VERSION 5.7 ;
BUSBITCHARS "[]" ;
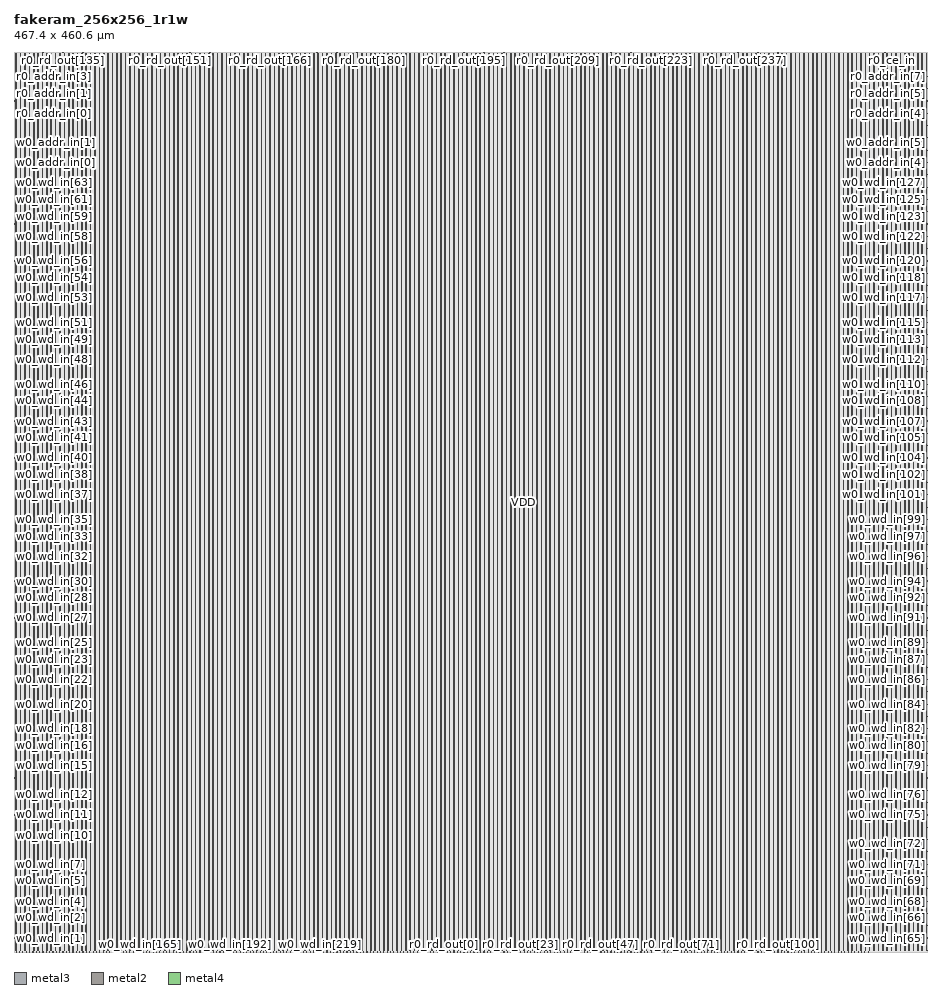
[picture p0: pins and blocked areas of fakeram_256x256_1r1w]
MACRO fakeram_256x256_1r1w
  FOREIGN fakeram_256x256_1r1w 0 0 ;
  SYMMETRY X Y R90 ;
  SIZE 467.400 BY 460.600 ;
  CLASS BLOCK ;
  PIN w0_wd_in[0]
    DIRECTION INPUT ;
    USE SIGNAL ;
    SHAPE ABUTMENT ;
    PORT
      LAYER metal3 ;
      RECT 0.000 0.805 0.210 0.875 ;
    END
  END w0_wd_in[0]
  PIN w0_wd_in[1]
    DIRECTION INPUT ;
    USE SIGNAL ;
    SHAPE ABUTMENT ;
    PORT
      LAYER metal3 ;
      RECT 0.000 7.105 0.210 7.175 ;
    END
  END w0_wd_in[1]
  PIN w0_wd_in[2]
    DIRECTION INPUT ;
    USE SIGNAL ;
    SHAPE ABUTMENT ;
    PORT
      LAYER metal3 ;
      RECT 0.000 13.405 0.210 13.475 ;
    END
  END w0_wd_in[2]
  PIN w0_wd_in[3]
    DIRECTION INPUT ;
    USE SIGNAL ;
    SHAPE ABUTMENT ;
    PORT
      LAYER metal3 ;
      RECT 0.000 19.705 0.210 19.775 ;
    END
  END w0_wd_in[3]
  PIN w0_wd_in[4]
    DIRECTION INPUT ;
    USE SIGNAL ;
    SHAPE ABUTMENT ;
    PORT
      LAYER metal3 ;
      RECT 0.000 26.005 0.210 26.075 ;
    END
  END w0_wd_in[4]
  PIN w0_wd_in[5]
    DIRECTION INPUT ;
    USE SIGNAL ;
    SHAPE ABUTMENT ;
    PORT
      LAYER metal3 ;
      RECT 0.000 32.305 0.210 32.375 ;
    END
  END w0_wd_in[5]
  PIN w0_wd_in[6]
    DIRECTION INPUT ;
    USE SIGNAL ;
    SHAPE ABUTMENT ;
    PORT
      LAYER metal3 ;
      RECT 0.000 38.605 0.210 38.675 ;
    END
  END w0_wd_in[6]
  PIN w0_wd_in[7]
    DIRECTION INPUT ;
    USE SIGNAL ;
    SHAPE ABUTMENT ;
    PORT
      LAYER metal3 ;
      RECT 0.000 44.905 0.210 44.975 ;
    END
  END w0_wd_in[7]
  PIN w0_wd_in[8]
    DIRECTION INPUT ;
    USE SIGNAL ;
    SHAPE ABUTMENT ;
    PORT
      LAYER metal3 ;
      RECT 0.000 51.205 0.210 51.275 ;
    END
  END w0_wd_in[8]
  PIN w0_wd_in[9]
    DIRECTION INPUT ;
    USE SIGNAL ;
    SHAPE ABUTMENT ;
    PORT
      LAYER metal3 ;
      RECT 0.000 57.505 0.210 57.575 ;
    END
  END w0_wd_in[9]
  PIN w0_wd_in[10]
    DIRECTION INPUT ;
    USE SIGNAL ;
    SHAPE ABUTMENT ;
    PORT
      LAYER metal3 ;
      RECT 0.000 63.805 0.210 63.875 ;
    END
  END w0_wd_in[10]
  PIN w0_wd_in[11]
    DIRECTION INPUT ;
    USE SIGNAL ;
    SHAPE ABUTMENT ;
    PORT
      LAYER metal3 ;
      RECT 0.000 70.105 0.210 70.175 ;
    END
  END w0_wd_in[11]
  PIN w0_wd_in[12]
    DIRECTION INPUT ;
    USE SIGNAL ;
    SHAPE ABUTMENT ;
    PORT
      LAYER metal3 ;
      RECT 0.000 76.405 0.210 76.475 ;
    END
  END w0_wd_in[12]
  PIN w0_wd_in[13]
    DIRECTION INPUT ;
    USE SIGNAL ;
    SHAPE ABUTMENT ;
    PORT
      LAYER metal3 ;
      RECT 0.000 82.705 0.210 82.775 ;
    END
  END w0_wd_in[13]
  PIN w0_wd_in[14]
    DIRECTION INPUT ;
    USE SIGNAL ;
    SHAPE ABUTMENT ;
    PORT
      LAYER metal3 ;
      RECT 0.000 89.005 0.210 89.075 ;
    END
  END w0_wd_in[14]
  PIN w0_wd_in[15]
    DIRECTION INPUT ;
    USE SIGNAL ;
    SHAPE ABUTMENT ;
    PORT
      LAYER metal3 ;
      RECT 0.000 95.305 0.210 95.375 ;
    END
  END w0_wd_in[15]
  PIN w0_wd_in[16]
    DIRECTION INPUT ;
    USE SIGNAL ;
    SHAPE ABUTMENT ;
    PORT
      LAYER metal3 ;
      RECT 0.000 101.605 0.210 101.675 ;
    END
  END w0_wd_in[16]
  PIN w0_wd_in[17]
    DIRECTION INPUT ;
    USE SIGNAL ;
    SHAPE ABUTMENT ;
    PORT
      LAYER metal3 ;
      RECT 0.000 107.905 0.210 107.975 ;
    END
  END w0_wd_in[17]
  PIN w0_wd_in[18]
    DIRECTION INPUT ;
    USE SIGNAL ;
    SHAPE ABUTMENT ;
    PORT
      LAYER metal3 ;
      RECT 0.000 114.205 0.210 114.275 ;
    END
  END w0_wd_in[18]
  PIN w0_wd_in[19]
    DIRECTION INPUT ;
    USE SIGNAL ;
    SHAPE ABUTMENT ;
    PORT
      LAYER metal3 ;
      RECT 0.000 120.505 0.210 120.575 ;
    END
  END w0_wd_in[19]
  PIN w0_wd_in[20]
    DIRECTION INPUT ;
    USE SIGNAL ;
    SHAPE ABUTMENT ;
    PORT
      LAYER metal3 ;
      RECT 0.000 126.805 0.210 126.875 ;
    END
  END w0_wd_in[20]
  PIN w0_wd_in[21]
    DIRECTION INPUT ;
    USE SIGNAL ;
    SHAPE ABUTMENT ;
    PORT
      LAYER metal3 ;
      RECT 0.000 133.105 0.210 133.175 ;
    END
  END w0_wd_in[21]
  PIN w0_wd_in[22]
    DIRECTION INPUT ;
    USE SIGNAL ;
    SHAPE ABUTMENT ;
    PORT
      LAYER metal3 ;
      RECT 0.000 139.405 0.210 139.475 ;
    END
  END w0_wd_in[22]
  PIN w0_wd_in[23]
    DIRECTION INPUT ;
    USE SIGNAL ;
    SHAPE ABUTMENT ;
    PORT
      LAYER metal3 ;
      RECT 0.000 145.705 0.210 145.775 ;
    END
  END w0_wd_in[23]
  PIN w0_wd_in[24]
    DIRECTION INPUT ;
    USE SIGNAL ;
    SHAPE ABUTMENT ;
    PORT
      LAYER metal3 ;
      RECT 0.000 152.005 0.210 152.075 ;
    END
  END w0_wd_in[24]
  PIN w0_wd_in[25]
    DIRECTION INPUT ;
    USE SIGNAL ;
    SHAPE ABUTMENT ;
    PORT
      LAYER metal3 ;
      RECT 0.000 158.305 0.210 158.375 ;
    END
  END w0_wd_in[25]
  PIN w0_wd_in[26]
    DIRECTION INPUT ;
    USE SIGNAL ;
    SHAPE ABUTMENT ;
    PORT
      LAYER metal3 ;
      RECT 0.000 164.605 0.210 164.675 ;
    END
  END w0_wd_in[26]
  PIN w0_wd_in[27]
    DIRECTION INPUT ;
    USE SIGNAL ;
    SHAPE ABUTMENT ;
    PORT
      LAYER metal3 ;
      RECT 0.000 170.905 0.210 170.975 ;
    END
  END w0_wd_in[27]
  PIN w0_wd_in[28]
    DIRECTION INPUT ;
    USE SIGNAL ;
    SHAPE ABUTMENT ;
    PORT
      LAYER metal3 ;
      RECT 0.000 177.205 0.210 177.275 ;
    END
  END w0_wd_in[28]
  PIN w0_wd_in[29]
    DIRECTION INPUT ;
    USE SIGNAL ;
    SHAPE ABUTMENT ;
    PORT
      LAYER metal3 ;
      RECT 0.000 183.505 0.210 183.575 ;
    END
  END w0_wd_in[29]
  PIN w0_wd_in[30]
    DIRECTION INPUT ;
    USE SIGNAL ;
    SHAPE ABUTMENT ;
    PORT
      LAYER metal3 ;
      RECT 0.000 189.805 0.210 189.875 ;
    END
  END w0_wd_in[30]
  PIN w0_wd_in[31]
    DIRECTION INPUT ;
    USE SIGNAL ;
    SHAPE ABUTMENT ;
    PORT
      LAYER metal3 ;
      RECT 0.000 196.105 0.210 196.175 ;
    END
  END w0_wd_in[31]
  PIN w0_wd_in[32]
    DIRECTION INPUT ;
    USE SIGNAL ;
    SHAPE ABUTMENT ;
    PORT
      LAYER metal3 ;
      RECT 0.000 202.405 0.210 202.475 ;
    END
  END w0_wd_in[32]
  PIN w0_wd_in[33]
    DIRECTION INPUT ;
    USE SIGNAL ;
    SHAPE ABUTMENT ;
    PORT
      LAYER metal3 ;
      RECT 0.000 208.705 0.210 208.775 ;
    END
  END w0_wd_in[33]
  PIN w0_wd_in[34]
    DIRECTION INPUT ;
    USE SIGNAL ;
    SHAPE ABUTMENT ;
    PORT
      LAYER metal3 ;
      RECT 0.000 215.005 0.210 215.075 ;
    END
  END w0_wd_in[34]
  PIN w0_wd_in[35]
    DIRECTION INPUT ;
    USE SIGNAL ;
    SHAPE ABUTMENT ;
    PORT
      LAYER metal3 ;
      RECT 0.000 221.305 0.210 221.375 ;
    END
  END w0_wd_in[35]
  PIN w0_wd_in[36]
    DIRECTION INPUT ;
    USE SIGNAL ;
    SHAPE ABUTMENT ;
    PORT
      LAYER metal3 ;
      RECT 0.000 227.605 0.210 227.675 ;
    END
  END w0_wd_in[36]
  PIN w0_wd_in[37]
    DIRECTION INPUT ;
    USE SIGNAL ;
    SHAPE ABUTMENT ;
    PORT
      LAYER metal3 ;
      RECT 0.000 233.905 0.210 233.975 ;
    END
  END w0_wd_in[37]
  PIN w0_wd_in[38]
    DIRECTION INPUT ;
    USE SIGNAL ;
    SHAPE ABUTMENT ;
    PORT
      LAYER metal3 ;
      RECT 0.000 240.205 0.210 240.275 ;
    END
  END w0_wd_in[38]
  PIN w0_wd_in[39]
    DIRECTION INPUT ;
    USE SIGNAL ;
    SHAPE ABUTMENT ;
    PORT
      LAYER metal3 ;
      RECT 0.000 246.505 0.210 246.575 ;
    END
  END w0_wd_in[39]
  PIN w0_wd_in[40]
    DIRECTION INPUT ;
    USE SIGNAL ;
    SHAPE ABUTMENT ;
    PORT
      LAYER metal3 ;
      RECT 0.000 252.805 0.210 252.875 ;
    END
  END w0_wd_in[40]
  PIN w0_wd_in[41]
    DIRECTION INPUT ;
    USE SIGNAL ;
    SHAPE ABUTMENT ;
    PORT
      LAYER metal3 ;
      RECT 0.000 259.105 0.210 259.175 ;
    END
  END w0_wd_in[41]
  PIN w0_wd_in[42]
    DIRECTION INPUT ;
    USE SIGNAL ;
    SHAPE ABUTMENT ;
    PORT
      LAYER metal3 ;
      RECT 0.000 265.405 0.210 265.475 ;
    END
  END w0_wd_in[42]
  PIN w0_wd_in[43]
    DIRECTION INPUT ;
    USE SIGNAL ;
    SHAPE ABUTMENT ;
    PORT
      LAYER metal3 ;
      RECT 0.000 271.705 0.210 271.775 ;
    END
  END w0_wd_in[43]
  PIN w0_wd_in[44]
    DIRECTION INPUT ;
    USE SIGNAL ;
    SHAPE ABUTMENT ;
    PORT
      LAYER metal3 ;
      RECT 0.000 278.005 0.210 278.075 ;
    END
  END w0_wd_in[44]
  PIN w0_wd_in[45]
    DIRECTION INPUT ;
    USE SIGNAL ;
    SHAPE ABUTMENT ;
    PORT
      LAYER metal3 ;
      RECT 0.000 284.305 0.210 284.375 ;
    END
  END w0_wd_in[45]
  PIN w0_wd_in[46]
    DIRECTION INPUT ;
    USE SIGNAL ;
    SHAPE ABUTMENT ;
    PORT
      LAYER metal3 ;
      RECT 0.000 290.605 0.210 290.675 ;
    END
  END w0_wd_in[46]
  PIN w0_wd_in[47]
    DIRECTION INPUT ;
    USE SIGNAL ;
    SHAPE ABUTMENT ;
    PORT
      LAYER metal3 ;
      RECT 0.000 296.905 0.210 296.975 ;
    END
  END w0_wd_in[47]
  PIN w0_wd_in[48]
    DIRECTION INPUT ;
    USE SIGNAL ;
    SHAPE ABUTMENT ;
    PORT
      LAYER metal3 ;
      RECT 0.000 303.205 0.210 303.275 ;
    END
  END w0_wd_in[48]
  PIN w0_wd_in[49]
    DIRECTION INPUT ;
    USE SIGNAL ;
    SHAPE ABUTMENT ;
    PORT
      LAYER metal3 ;
      RECT 0.000 309.505 0.210 309.575 ;
    END
  END w0_wd_in[49]
  PIN w0_wd_in[50]
    DIRECTION INPUT ;
    USE SIGNAL ;
    SHAPE ABUTMENT ;
    PORT
      LAYER metal3 ;
      RECT 0.000 315.805 0.210 315.875 ;
    END
  END w0_wd_in[50]
  PIN w0_wd_in[51]
    DIRECTION INPUT ;
    USE SIGNAL ;
    SHAPE ABUTMENT ;
    PORT
      LAYER metal3 ;
      RECT 0.000 322.105 0.210 322.175 ;
    END
  END w0_wd_in[51]
  PIN w0_wd_in[52]
    DIRECTION INPUT ;
    USE SIGNAL ;
    SHAPE ABUTMENT ;
    PORT
      LAYER metal3 ;
      RECT 0.000 328.405 0.210 328.475 ;
    END
  END w0_wd_in[52]
  PIN w0_wd_in[53]
    DIRECTION INPUT ;
    USE SIGNAL ;
    SHAPE ABUTMENT ;
    PORT
      LAYER metal3 ;
      RECT 0.000 334.705 0.210 334.775 ;
    END
  END w0_wd_in[53]
  PIN w0_wd_in[54]
    DIRECTION INPUT ;
    USE SIGNAL ;
    SHAPE ABUTMENT ;
    PORT
      LAYER metal3 ;
      RECT 0.000 341.005 0.210 341.075 ;
    END
  END w0_wd_in[54]
  PIN w0_wd_in[55]
    DIRECTION INPUT ;
    USE SIGNAL ;
    SHAPE ABUTMENT ;
    PORT
      LAYER metal3 ;
      RECT 0.000 347.305 0.210 347.375 ;
    END
  END w0_wd_in[55]
  PIN w0_wd_in[56]
    DIRECTION INPUT ;
    USE SIGNAL ;
    SHAPE ABUTMENT ;
    PORT
      LAYER metal3 ;
      RECT 0.000 353.605 0.210 353.675 ;
    END
  END w0_wd_in[56]
  PIN w0_wd_in[57]
    DIRECTION INPUT ;
    USE SIGNAL ;
    SHAPE ABUTMENT ;
    PORT
      LAYER metal3 ;
      RECT 0.000 359.905 0.210 359.975 ;
    END
  END w0_wd_in[57]
  PIN w0_wd_in[58]
    DIRECTION INPUT ;
    USE SIGNAL ;
    SHAPE ABUTMENT ;
    PORT
      LAYER metal3 ;
      RECT 0.000 366.205 0.210 366.275 ;
    END
  END w0_wd_in[58]
  PIN w0_wd_in[59]
    DIRECTION INPUT ;
    USE SIGNAL ;
    SHAPE ABUTMENT ;
    PORT
      LAYER metal3 ;
      RECT 0.000 372.505 0.210 372.575 ;
    END
  END w0_wd_in[59]
  PIN w0_wd_in[60]
    DIRECTION INPUT ;
    USE SIGNAL ;
    SHAPE ABUTMENT ;
    PORT
      LAYER metal3 ;
      RECT 0.000 378.805 0.210 378.875 ;
    END
  END w0_wd_in[60]
  PIN w0_wd_in[61]
    DIRECTION INPUT ;
    USE SIGNAL ;
    SHAPE ABUTMENT ;
    PORT
      LAYER metal3 ;
      RECT 0.000 385.105 0.210 385.175 ;
    END
  END w0_wd_in[61]
  PIN w0_wd_in[62]
    DIRECTION INPUT ;
    USE SIGNAL ;
    SHAPE ABUTMENT ;
    PORT
      LAYER metal3 ;
      RECT 0.000 391.405 0.210 391.475 ;
    END
  END w0_wd_in[62]
  PIN w0_wd_in[63]
    DIRECTION INPUT ;
    USE SIGNAL ;
    SHAPE ABUTMENT ;
    PORT
      LAYER metal3 ;
      RECT 0.000 397.705 0.210 397.775 ;
    END
  END w0_wd_in[63]
  PIN w0_wd_in[64]
    DIRECTION INPUT ;
    USE SIGNAL ;
    SHAPE ABUTMENT ;
    PORT
      LAYER metal3 ;
      RECT 467.190 0.805 467.400 0.875 ;
    END
  END w0_wd_in[64]
  PIN w0_wd_in[65]
    DIRECTION INPUT ;
    USE SIGNAL ;
    SHAPE ABUTMENT ;
    PORT
      LAYER metal3 ;
      RECT 467.190 7.105 467.400 7.175 ;
    END
  END w0_wd_in[65]
  PIN w0_wd_in[66]
    DIRECTION INPUT ;
    USE SIGNAL ;
    SHAPE ABUTMENT ;
    PORT
      LAYER metal3 ;
      RECT 467.190 13.405 467.400 13.475 ;
    END
  END w0_wd_in[66]
  PIN w0_wd_in[67]
    DIRECTION INPUT ;
    USE SIGNAL ;
    SHAPE ABUTMENT ;
    PORT
      LAYER metal3 ;
      RECT 467.190 19.705 467.400 19.775 ;
    END
  END w0_wd_in[67]
  PIN w0_wd_in[68]
    DIRECTION INPUT ;
    USE SIGNAL ;
    SHAPE ABUTMENT ;
    PORT
      LAYER metal3 ;
      RECT 467.190 26.005 467.400 26.075 ;
    END
  END w0_wd_in[68]
  PIN w0_wd_in[69]
    DIRECTION INPUT ;
    USE SIGNAL ;
    SHAPE ABUTMENT ;
    PORT
      LAYER metal3 ;
      RECT 467.190 32.305 467.400 32.375 ;
    END
  END w0_wd_in[69]
  PIN w0_wd_in[70]
    DIRECTION INPUT ;
    USE SIGNAL ;
    SHAPE ABUTMENT ;
    PORT
      LAYER metal3 ;
      RECT 467.190 38.605 467.400 38.675 ;
    END
  END w0_wd_in[70]
  PIN w0_wd_in[71]
    DIRECTION INPUT ;
    USE SIGNAL ;
    SHAPE ABUTMENT ;
    PORT
      LAYER metal3 ;
      RECT 467.190 44.905 467.400 44.975 ;
    END
  END w0_wd_in[71]
  PIN w0_wd_in[72]
    DIRECTION INPUT ;
    USE SIGNAL ;
    SHAPE ABUTMENT ;
    PORT
      LAYER metal3 ;
      RECT 467.190 51.205 467.400 51.275 ;
    END
  END w0_wd_in[72]
  PIN w0_wd_in[73]
    DIRECTION INPUT ;
    USE SIGNAL ;
    SHAPE ABUTMENT ;
    PORT
      LAYER metal3 ;
      RECT 467.190 57.505 467.400 57.575 ;
    END
  END w0_wd_in[73]
  PIN w0_wd_in[74]
    DIRECTION INPUT ;
    USE SIGNAL ;
    SHAPE ABUTMENT ;
    PORT
      LAYER metal3 ;
      RECT 467.190 63.805 467.400 63.875 ;
    END
  END w0_wd_in[74]
  PIN w0_wd_in[75]
    DIRECTION INPUT ;
    USE SIGNAL ;
    SHAPE ABUTMENT ;
    PORT
      LAYER metal3 ;
      RECT 467.190 70.105 467.400 70.175 ;
    END
  END w0_wd_in[75]
  PIN w0_wd_in[76]
    DIRECTION INPUT ;
    USE SIGNAL ;
    SHAPE ABUTMENT ;
    PORT
      LAYER metal3 ;
      RECT 467.190 76.405 467.400 76.475 ;
    END
  END w0_wd_in[76]
  PIN w0_wd_in[77]
    DIRECTION INPUT ;
    USE SIGNAL ;
    SHAPE ABUTMENT ;
    PORT
      LAYER metal3 ;
      RECT 467.190 82.705 467.400 82.775 ;
    END
  END w0_wd_in[77]
  PIN w0_wd_in[78]
    DIRECTION INPUT ;
    USE SIGNAL ;
    SHAPE ABUTMENT ;
    PORT
      LAYER metal3 ;
      RECT 467.190 89.005 467.400 89.075 ;
    END
  END w0_wd_in[78]
  PIN w0_wd_in[79]
    DIRECTION INPUT ;
    USE SIGNAL ;
    SHAPE ABUTMENT ;
    PORT
      LAYER metal3 ;
      RECT 467.190 95.305 467.400 95.375 ;
    END
  END w0_wd_in[79]
  PIN w0_wd_in[80]
    DIRECTION INPUT ;
    USE SIGNAL ;
    SHAPE ABUTMENT ;
    PORT
      LAYER metal3 ;
      RECT 467.190 101.605 467.400 101.675 ;
    END
  END w0_wd_in[80]
  PIN w0_wd_in[81]
    DIRECTION INPUT ;
    USE SIGNAL ;
    SHAPE ABUTMENT ;
    PORT
      LAYER metal3 ;
      RECT 467.190 107.905 467.400 107.975 ;
    END
  END w0_wd_in[81]
  PIN w0_wd_in[82]
    DIRECTION INPUT ;
    USE SIGNAL ;
    SHAPE ABUTMENT ;
    PORT
      LAYER metal3 ;
      RECT 467.190 114.205 467.400 114.275 ;
    END
  END w0_wd_in[82]
  PIN w0_wd_in[83]
    DIRECTION INPUT ;
    USE SIGNAL ;
    SHAPE ABUTMENT ;
    PORT
      LAYER metal3 ;
      RECT 467.190 120.505 467.400 120.575 ;
    END
  END w0_wd_in[83]
  PIN w0_wd_in[84]
    DIRECTION INPUT ;
    USE SIGNAL ;
    SHAPE ABUTMENT ;
    PORT
      LAYER metal3 ;
      RECT 467.190 126.805 467.400 126.875 ;
    END
  END w0_wd_in[84]
  PIN w0_wd_in[85]
    DIRECTION INPUT ;
    USE SIGNAL ;
    SHAPE ABUTMENT ;
    PORT
      LAYER metal3 ;
      RECT 467.190 133.105 467.400 133.175 ;
    END
  END w0_wd_in[85]
  PIN w0_wd_in[86]
    DIRECTION INPUT ;
    USE SIGNAL ;
    SHAPE ABUTMENT ;
    PORT
      LAYER metal3 ;
      RECT 467.190 139.405 467.400 139.475 ;
    END
  END w0_wd_in[86]
  PIN w0_wd_in[87]
    DIRECTION INPUT ;
    USE SIGNAL ;
    SHAPE ABUTMENT ;
    PORT
      LAYER metal3 ;
      RECT 467.190 145.705 467.400 145.775 ;
    END
  END w0_wd_in[87]
  PIN w0_wd_in[88]
    DIRECTION INPUT ;
    USE SIGNAL ;
    SHAPE ABUTMENT ;
    PORT
      LAYER metal3 ;
      RECT 467.190 152.005 467.400 152.075 ;
    END
  END w0_wd_in[88]
  PIN w0_wd_in[89]
    DIRECTION INPUT ;
    USE SIGNAL ;
    SHAPE ABUTMENT ;
    PORT
      LAYER metal3 ;
      RECT 467.190 158.305 467.400 158.375 ;
    END
  END w0_wd_in[89]
  PIN w0_wd_in[90]
    DIRECTION INPUT ;
    USE SIGNAL ;
    SHAPE ABUTMENT ;
    PORT
      LAYER metal3 ;
      RECT 467.190 164.605 467.400 164.675 ;
    END
  END w0_wd_in[90]
  PIN w0_wd_in[91]
    DIRECTION INPUT ;
    USE SIGNAL ;
    SHAPE ABUTMENT ;
    PORT
      LAYER metal3 ;
      RECT 467.190 170.905 467.400 170.975 ;
    END
  END w0_wd_in[91]
  PIN w0_wd_in[92]
    DIRECTION INPUT ;
    USE SIGNAL ;
    SHAPE ABUTMENT ;
    PORT
      LAYER metal3 ;
      RECT 467.190 177.205 467.400 177.275 ;
    END
  END w0_wd_in[92]
  PIN w0_wd_in[93]
    DIRECTION INPUT ;
    USE SIGNAL ;
    SHAPE ABUTMENT ;
    PORT
      LAYER metal3 ;
      RECT 467.190 183.505 467.400 183.575 ;
    END
  END w0_wd_in[93]
  PIN w0_wd_in[94]
    DIRECTION INPUT ;
    USE SIGNAL ;
    SHAPE ABUTMENT ;
    PORT
      LAYER metal3 ;
      RECT 467.190 189.805 467.400 189.875 ;
    END
  END w0_wd_in[94]
  PIN w0_wd_in[95]
    DIRECTION INPUT ;
    USE SIGNAL ;
    SHAPE ABUTMENT ;
    PORT
      LAYER metal3 ;
      RECT 467.190 196.105 467.400 196.175 ;
    END
  END w0_wd_in[95]
  PIN w0_wd_in[96]
    DIRECTION INPUT ;
    USE SIGNAL ;
    SHAPE ABUTMENT ;
    PORT
      LAYER metal3 ;
      RECT 467.190 202.405 467.400 202.475 ;
    END
  END w0_wd_in[96]
  PIN w0_wd_in[97]
    DIRECTION INPUT ;
    USE SIGNAL ;
    SHAPE ABUTMENT ;
    PORT
      LAYER metal3 ;
      RECT 467.190 208.705 467.400 208.775 ;
    END
  END w0_wd_in[97]
  PIN w0_wd_in[98]
    DIRECTION INPUT ;
    USE SIGNAL ;
    SHAPE ABUTMENT ;
    PORT
      LAYER metal3 ;
      RECT 467.190 215.005 467.400 215.075 ;
    END
  END w0_wd_in[98]
  PIN w0_wd_in[99]
    DIRECTION INPUT ;
    USE SIGNAL ;
    SHAPE ABUTMENT ;
    PORT
      LAYER metal3 ;
      RECT 467.190 221.305 467.400 221.375 ;
    END
  END w0_wd_in[99]
  PIN w0_wd_in[100]
    DIRECTION INPUT ;
    USE SIGNAL ;
    SHAPE ABUTMENT ;
    PORT
      LAYER metal3 ;
      RECT 467.190 227.605 467.400 227.675 ;
    END
  END w0_wd_in[100]
  PIN w0_wd_in[101]
    DIRECTION INPUT ;
    USE SIGNAL ;
    SHAPE ABUTMENT ;
    PORT
      LAYER metal3 ;
      RECT 467.190 233.905 467.400 233.975 ;
    END
  END w0_wd_in[101]
  PIN w0_wd_in[102]
    DIRECTION INPUT ;
    USE SIGNAL ;
    SHAPE ABUTMENT ;
    PORT
      LAYER metal3 ;
      RECT 467.190 240.205 467.400 240.275 ;
    END
  END w0_wd_in[102]
  PIN w0_wd_in[103]
    DIRECTION INPUT ;
    USE SIGNAL ;
    SHAPE ABUTMENT ;
    PORT
      LAYER metal3 ;
      RECT 467.190 246.505 467.400 246.575 ;
    END
  END w0_wd_in[103]
  PIN w0_wd_in[104]
    DIRECTION INPUT ;
    USE SIGNAL ;
    SHAPE ABUTMENT ;
    PORT
      LAYER metal3 ;
      RECT 467.190 252.805 467.400 252.875 ;
    END
  END w0_wd_in[104]
  PIN w0_wd_in[105]
    DIRECTION INPUT ;
    USE SIGNAL ;
    SHAPE ABUTMENT ;
    PORT
      LAYER metal3 ;
      RECT 467.190 259.105 467.400 259.175 ;
    END
  END w0_wd_in[105]
  PIN w0_wd_in[106]
    DIRECTION INPUT ;
    USE SIGNAL ;
    SHAPE ABUTMENT ;
    PORT
      LAYER metal3 ;
      RECT 467.190 265.405 467.400 265.475 ;
    END
  END w0_wd_in[106]
  PIN w0_wd_in[107]
    DIRECTION INPUT ;
    USE SIGNAL ;
    SHAPE ABUTMENT ;
    PORT
      LAYER metal3 ;
      RECT 467.190 271.705 467.400 271.775 ;
    END
  END w0_wd_in[107]
  PIN w0_wd_in[108]
    DIRECTION INPUT ;
    USE SIGNAL ;
    SHAPE ABUTMENT ;
    PORT
      LAYER metal3 ;
      RECT 467.190 278.005 467.400 278.075 ;
    END
  END w0_wd_in[108]
  PIN w0_wd_in[109]
    DIRECTION INPUT ;
    USE SIGNAL ;
    SHAPE ABUTMENT ;
    PORT
      LAYER metal3 ;
      RECT 467.190 284.305 467.400 284.375 ;
    END
  END w0_wd_in[109]
  PIN w0_wd_in[110]
    DIRECTION INPUT ;
    USE SIGNAL ;
    SHAPE ABUTMENT ;
    PORT
      LAYER metal3 ;
      RECT 467.190 290.605 467.400 290.675 ;
    END
  END w0_wd_in[110]
  PIN w0_wd_in[111]
    DIRECTION INPUT ;
    USE SIGNAL ;
    SHAPE ABUTMENT ;
    PORT
      LAYER metal3 ;
      RECT 467.190 296.905 467.400 296.975 ;
    END
  END w0_wd_in[111]
  PIN w0_wd_in[112]
    DIRECTION INPUT ;
    USE SIGNAL ;
    SHAPE ABUTMENT ;
    PORT
      LAYER metal3 ;
      RECT 467.190 303.205 467.400 303.275 ;
    END
  END w0_wd_in[112]
  PIN w0_wd_in[113]
    DIRECTION INPUT ;
    USE SIGNAL ;
    SHAPE ABUTMENT ;
    PORT
      LAYER metal3 ;
      RECT 467.190 309.505 467.400 309.575 ;
    END
  END w0_wd_in[113]
  PIN w0_wd_in[114]
    DIRECTION INPUT ;
    USE SIGNAL ;
    SHAPE ABUTMENT ;
    PORT
      LAYER metal3 ;
      RECT 467.190 315.805 467.400 315.875 ;
    END
  END w0_wd_in[114]
  PIN w0_wd_in[115]
    DIRECTION INPUT ;
    USE SIGNAL ;
    SHAPE ABUTMENT ;
    PORT
      LAYER metal3 ;
      RECT 467.190 322.105 467.400 322.175 ;
    END
  END w0_wd_in[115]
  PIN w0_wd_in[116]
    DIRECTION INPUT ;
    USE SIGNAL ;
    SHAPE ABUTMENT ;
    PORT
      LAYER metal3 ;
      RECT 467.190 328.405 467.400 328.475 ;
    END
  END w0_wd_in[116]
  PIN w0_wd_in[117]
    DIRECTION INPUT ;
    USE SIGNAL ;
    SHAPE ABUTMENT ;
    PORT
      LAYER metal3 ;
      RECT 467.190 334.705 467.400 334.775 ;
    END
  END w0_wd_in[117]
  PIN w0_wd_in[118]
    DIRECTION INPUT ;
    USE SIGNAL ;
    SHAPE ABUTMENT ;
    PORT
      LAYER metal3 ;
      RECT 467.190 341.005 467.400 341.075 ;
    END
  END w0_wd_in[118]
  PIN w0_wd_in[119]
    DIRECTION INPUT ;
    USE SIGNAL ;
    SHAPE ABUTMENT ;
    PORT
      LAYER metal3 ;
      RECT 467.190 347.305 467.400 347.375 ;
    END
  END w0_wd_in[119]
  PIN w0_wd_in[120]
    DIRECTION INPUT ;
    USE SIGNAL ;
    SHAPE ABUTMENT ;
    PORT
      LAYER metal3 ;
      RECT 467.190 353.605 467.400 353.675 ;
    END
  END w0_wd_in[120]
  PIN w0_wd_in[121]
    DIRECTION INPUT ;
    USE SIGNAL ;
    SHAPE ABUTMENT ;
    PORT
      LAYER metal3 ;
      RECT 467.190 359.905 467.400 359.975 ;
    END
  END w0_wd_in[121]
  PIN w0_wd_in[122]
    DIRECTION INPUT ;
    USE SIGNAL ;
    SHAPE ABUTMENT ;
    PORT
      LAYER metal3 ;
      RECT 467.190 366.205 467.400 366.275 ;
    END
  END w0_wd_in[122]
  PIN w0_wd_in[123]
    DIRECTION INPUT ;
    USE SIGNAL ;
    SHAPE ABUTMENT ;
    PORT
      LAYER metal3 ;
      RECT 467.190 372.505 467.400 372.575 ;
    END
  END w0_wd_in[123]
  PIN w0_wd_in[124]
    DIRECTION INPUT ;
    USE SIGNAL ;
    SHAPE ABUTMENT ;
    PORT
      LAYER metal3 ;
      RECT 467.190 378.805 467.400 378.875 ;
    END
  END w0_wd_in[124]
  PIN w0_wd_in[125]
    DIRECTION INPUT ;
    USE SIGNAL ;
    SHAPE ABUTMENT ;
    PORT
      LAYER metal3 ;
      RECT 467.190 385.105 467.400 385.175 ;
    END
  END w0_wd_in[125]
  PIN w0_wd_in[126]
    DIRECTION INPUT ;
    USE SIGNAL ;
    SHAPE ABUTMENT ;
    PORT
      LAYER metal3 ;
      RECT 467.190 391.405 467.400 391.475 ;
    END
  END w0_wd_in[126]
  PIN w0_wd_in[127]
    DIRECTION INPUT ;
    USE SIGNAL ;
    SHAPE ABUTMENT ;
    PORT
      LAYER metal3 ;
      RECT 467.190 397.705 467.400 397.775 ;
    END
  END w0_wd_in[127]
  PIN w0_wd_in[128]
    DIRECTION OUTPUT ;
    USE SIGNAL ;
    SHAPE ABUTMENT ;
    PORT
      LAYER metal2 ;
      RECT 1.105 0.000 1.175 0.210 ;
    END
  END w0_wd_in[128]
  PIN w0_wd_in[129]
    DIRECTION OUTPUT ;
    USE SIGNAL ;
    SHAPE ABUTMENT ;
    PORT
      LAYER metal2 ;
      RECT 2.815 0.000 2.885 0.210 ;
    END
  END w0_wd_in[129]
  PIN w0_wd_in[130]
    DIRECTION OUTPUT ;
    USE SIGNAL ;
    SHAPE ABUTMENT ;
    PORT
      LAYER metal2 ;
      RECT 4.525 0.000 4.595 0.210 ;
    END
  END w0_wd_in[130]
  PIN w0_wd_in[131]
    DIRECTION OUTPUT ;
    USE SIGNAL ;
    SHAPE ABUTMENT ;
    PORT
      LAYER metal2 ;
      RECT 6.235 0.000 6.305 0.210 ;
    END
  END w0_wd_in[131]
  PIN w0_wd_in[132]
    DIRECTION OUTPUT ;
    USE SIGNAL ;
    SHAPE ABUTMENT ;
    PORT
      LAYER metal2 ;
      RECT 7.945 0.000 8.015 0.210 ;
    END
  END w0_wd_in[132]
  PIN w0_wd_in[133]
    DIRECTION OUTPUT ;
    USE SIGNAL ;
    SHAPE ABUTMENT ;
    PORT
      LAYER metal2 ;
      RECT 9.655 0.000 9.725 0.210 ;
    END
  END w0_wd_in[133]
  PIN w0_wd_in[134]
    DIRECTION OUTPUT ;
    USE SIGNAL ;
    SHAPE ABUTMENT ;
    PORT
      LAYER metal2 ;
      RECT 11.365 0.000 11.435 0.210 ;
    END
  END w0_wd_in[134]
  PIN w0_wd_in[135]
    DIRECTION OUTPUT ;
    USE SIGNAL ;
    SHAPE ABUTMENT ;
    PORT
      LAYER metal2 ;
      RECT 13.075 0.000 13.145 0.210 ;
    END
  END w0_wd_in[135]
  PIN w0_wd_in[136]
    DIRECTION OUTPUT ;
    USE SIGNAL ;
    SHAPE ABUTMENT ;
    PORT
      LAYER metal2 ;
      RECT 14.785 0.000 14.855 0.210 ;
    END
  END w0_wd_in[136]
  PIN w0_wd_in[137]
    DIRECTION OUTPUT ;
    USE SIGNAL ;
    SHAPE ABUTMENT ;
    PORT
      LAYER metal2 ;
      RECT 16.495 0.000 16.565 0.210 ;
    END
  END w0_wd_in[137]
  PIN w0_wd_in[138]
    DIRECTION OUTPUT ;
    USE SIGNAL ;
    SHAPE ABUTMENT ;
    PORT
      LAYER metal2 ;
      RECT 18.205 0.000 18.275 0.210 ;
    END
  END w0_wd_in[138]
  PIN w0_wd_in[139]
    DIRECTION OUTPUT ;
    USE SIGNAL ;
    SHAPE ABUTMENT ;
    PORT
      LAYER metal2 ;
      RECT 19.915 0.000 19.985 0.210 ;
    END
  END w0_wd_in[139]
  PIN w0_wd_in[140]
    DIRECTION OUTPUT ;
    USE SIGNAL ;
    SHAPE ABUTMENT ;
    PORT
      LAYER metal2 ;
      RECT 21.625 0.000 21.695 0.210 ;
    END
  END w0_wd_in[140]
  PIN w0_wd_in[141]
    DIRECTION OUTPUT ;
    USE SIGNAL ;
    SHAPE ABUTMENT ;
    PORT
      LAYER metal2 ;
      RECT 23.335 0.000 23.405 0.210 ;
    END
  END w0_wd_in[141]
  PIN w0_wd_in[142]
    DIRECTION OUTPUT ;
    USE SIGNAL ;
    SHAPE ABUTMENT ;
    PORT
      LAYER metal2 ;
      RECT 25.045 0.000 25.115 0.210 ;
    END
  END w0_wd_in[142]
  PIN w0_wd_in[143]
    DIRECTION OUTPUT ;
    USE SIGNAL ;
    SHAPE ABUTMENT ;
    PORT
      LAYER metal2 ;
      RECT 26.755 0.000 26.825 0.210 ;
    END
  END w0_wd_in[143]
  PIN w0_wd_in[144]
    DIRECTION OUTPUT ;
    USE SIGNAL ;
    SHAPE ABUTMENT ;
    PORT
      LAYER metal2 ;
      RECT 28.465 0.000 28.535 0.210 ;
    END
  END w0_wd_in[144]
  PIN w0_wd_in[145]
    DIRECTION OUTPUT ;
    USE SIGNAL ;
    SHAPE ABUTMENT ;
    PORT
      LAYER metal2 ;
      RECT 30.175 0.000 30.245 0.210 ;
    END
  END w0_wd_in[145]
  PIN w0_wd_in[146]
    DIRECTION OUTPUT ;
    USE SIGNAL ;
    SHAPE ABUTMENT ;
    PORT
      LAYER metal2 ;
      RECT 31.885 0.000 31.955 0.210 ;
    END
  END w0_wd_in[146]
  PIN w0_wd_in[147]
    DIRECTION OUTPUT ;
    USE SIGNAL ;
    SHAPE ABUTMENT ;
    PORT
      LAYER metal2 ;
      RECT 33.595 0.000 33.665 0.210 ;
    END
  END w0_wd_in[147]
  PIN w0_wd_in[148]
    DIRECTION OUTPUT ;
    USE SIGNAL ;
    SHAPE ABUTMENT ;
    PORT
      LAYER metal2 ;
      RECT 35.305 0.000 35.375 0.210 ;
    END
  END w0_wd_in[148]
  PIN w0_wd_in[149]
    DIRECTION OUTPUT ;
    USE SIGNAL ;
    SHAPE ABUTMENT ;
    PORT
      LAYER metal2 ;
      RECT 37.015 0.000 37.085 0.210 ;
    END
  END w0_wd_in[149]
  PIN w0_wd_in[150]
    DIRECTION OUTPUT ;
    USE SIGNAL ;
    SHAPE ABUTMENT ;
    PORT
      LAYER metal2 ;
      RECT 38.725 0.000 38.795 0.210 ;
    END
  END w0_wd_in[150]
  PIN w0_wd_in[151]
    DIRECTION OUTPUT ;
    USE SIGNAL ;
    SHAPE ABUTMENT ;
    PORT
      LAYER metal2 ;
      RECT 40.435 0.000 40.505 0.210 ;
    END
  END w0_wd_in[151]
  PIN w0_wd_in[152]
    DIRECTION OUTPUT ;
    USE SIGNAL ;
    SHAPE ABUTMENT ;
    PORT
      LAYER metal2 ;
      RECT 42.145 0.000 42.215 0.210 ;
    END
  END w0_wd_in[152]
  PIN w0_wd_in[153]
    DIRECTION OUTPUT ;
    USE SIGNAL ;
    SHAPE ABUTMENT ;
    PORT
      LAYER metal2 ;
      RECT 43.855 0.000 43.925 0.210 ;
    END
  END w0_wd_in[153]
  PIN w0_wd_in[154]
    DIRECTION OUTPUT ;
    USE SIGNAL ;
    SHAPE ABUTMENT ;
    PORT
      LAYER metal2 ;
      RECT 45.565 0.000 45.635 0.210 ;
    END
  END w0_wd_in[154]
  PIN w0_wd_in[155]
    DIRECTION OUTPUT ;
    USE SIGNAL ;
    SHAPE ABUTMENT ;
    PORT
      LAYER metal2 ;
      RECT 47.275 0.000 47.345 0.210 ;
    END
  END w0_wd_in[155]
  PIN w0_wd_in[156]
    DIRECTION OUTPUT ;
    USE SIGNAL ;
    SHAPE ABUTMENT ;
    PORT
      LAYER metal2 ;
      RECT 48.985 0.000 49.055 0.210 ;
    END
  END w0_wd_in[156]
  PIN w0_wd_in[157]
    DIRECTION OUTPUT ;
    USE SIGNAL ;
    SHAPE ABUTMENT ;
    PORT
      LAYER metal2 ;
      RECT 50.695 0.000 50.765 0.210 ;
    END
  END w0_wd_in[157]
  PIN w0_wd_in[158]
    DIRECTION OUTPUT ;
    USE SIGNAL ;
    SHAPE ABUTMENT ;
    PORT
      LAYER metal2 ;
      RECT 52.405 0.000 52.475 0.210 ;
    END
  END w0_wd_in[158]
  PIN w0_wd_in[159]
    DIRECTION OUTPUT ;
    USE SIGNAL ;
    SHAPE ABUTMENT ;
    PORT
      LAYER metal2 ;
      RECT 54.115 0.000 54.185 0.210 ;
    END
  END w0_wd_in[159]
  PIN w0_wd_in[160]
    DIRECTION OUTPUT ;
    USE SIGNAL ;
    SHAPE ABUTMENT ;
    PORT
      LAYER metal2 ;
      RECT 55.825 0.000 55.895 0.210 ;
    END
  END w0_wd_in[160]
  PIN w0_wd_in[161]
    DIRECTION OUTPUT ;
    USE SIGNAL ;
    SHAPE ABUTMENT ;
    PORT
      LAYER metal2 ;
      RECT 57.535 0.000 57.605 0.210 ;
    END
  END w0_wd_in[161]
  PIN w0_wd_in[162]
    DIRECTION OUTPUT ;
    USE SIGNAL ;
    SHAPE ABUTMENT ;
    PORT
      LAYER metal2 ;
      RECT 59.245 0.000 59.315 0.210 ;
    END
  END w0_wd_in[162]
  PIN w0_wd_in[163]
    DIRECTION OUTPUT ;
    USE SIGNAL ;
    SHAPE ABUTMENT ;
    PORT
      LAYER metal2 ;
      RECT 60.955 0.000 61.025 0.210 ;
    END
  END w0_wd_in[163]
  PIN w0_wd_in[164]
    DIRECTION OUTPUT ;
    USE SIGNAL ;
    SHAPE ABUTMENT ;
    PORT
      LAYER metal2 ;
      RECT 62.665 0.000 62.735 0.210 ;
    END
  END w0_wd_in[164]
  PIN w0_wd_in[165]
    DIRECTION OUTPUT ;
    USE SIGNAL ;
    SHAPE ABUTMENT ;
    PORT
      LAYER metal2 ;
      RECT 64.375 0.000 64.445 0.210 ;
    END
  END w0_wd_in[165]
  PIN w0_wd_in[166]
    DIRECTION OUTPUT ;
    USE SIGNAL ;
    SHAPE ABUTMENT ;
    PORT
      LAYER metal2 ;
      RECT 66.085 0.000 66.155 0.210 ;
    END
  END w0_wd_in[166]
  PIN w0_wd_in[167]
    DIRECTION OUTPUT ;
    USE SIGNAL ;
    SHAPE ABUTMENT ;
    PORT
      LAYER metal2 ;
      RECT 67.795 0.000 67.865 0.210 ;
    END
  END w0_wd_in[167]
  PIN w0_wd_in[168]
    DIRECTION OUTPUT ;
    USE SIGNAL ;
    SHAPE ABUTMENT ;
    PORT
      LAYER metal2 ;
      RECT 69.505 0.000 69.575 0.210 ;
    END
  END w0_wd_in[168]
  PIN w0_wd_in[169]
    DIRECTION OUTPUT ;
    USE SIGNAL ;
    SHAPE ABUTMENT ;
    PORT
      LAYER metal2 ;
      RECT 71.215 0.000 71.285 0.210 ;
    END
  END w0_wd_in[169]
  PIN w0_wd_in[170]
    DIRECTION OUTPUT ;
    USE SIGNAL ;
    SHAPE ABUTMENT ;
    PORT
      LAYER metal2 ;
      RECT 72.925 0.000 72.995 0.210 ;
    END
  END w0_wd_in[170]
  PIN w0_wd_in[171]
    DIRECTION OUTPUT ;
    USE SIGNAL ;
    SHAPE ABUTMENT ;
    PORT
      LAYER metal2 ;
      RECT 74.635 0.000 74.705 0.210 ;
    END
  END w0_wd_in[171]
  PIN w0_wd_in[172]
    DIRECTION OUTPUT ;
    USE SIGNAL ;
    SHAPE ABUTMENT ;
    PORT
      LAYER metal2 ;
      RECT 76.345 0.000 76.415 0.210 ;
    END
  END w0_wd_in[172]
  PIN w0_wd_in[173]
    DIRECTION OUTPUT ;
    USE SIGNAL ;
    SHAPE ABUTMENT ;
    PORT
      LAYER metal2 ;
      RECT 78.055 0.000 78.125 0.210 ;
    END
  END w0_wd_in[173]
  PIN w0_wd_in[174]
    DIRECTION OUTPUT ;
    USE SIGNAL ;
    SHAPE ABUTMENT ;
    PORT
      LAYER metal2 ;
      RECT 79.765 0.000 79.835 0.210 ;
    END
  END w0_wd_in[174]
  PIN w0_wd_in[175]
    DIRECTION OUTPUT ;
    USE SIGNAL ;
    SHAPE ABUTMENT ;
    PORT
      LAYER metal2 ;
      RECT 81.475 0.000 81.545 0.210 ;
    END
  END w0_wd_in[175]
  PIN w0_wd_in[176]
    DIRECTION OUTPUT ;
    USE SIGNAL ;
    SHAPE ABUTMENT ;
    PORT
      LAYER metal2 ;
      RECT 83.185 0.000 83.255 0.210 ;
    END
  END w0_wd_in[176]
  PIN w0_wd_in[177]
    DIRECTION OUTPUT ;
    USE SIGNAL ;
    SHAPE ABUTMENT ;
    PORT
      LAYER metal2 ;
      RECT 84.895 0.000 84.965 0.210 ;
    END
  END w0_wd_in[177]
  PIN w0_wd_in[178]
    DIRECTION OUTPUT ;
    USE SIGNAL ;
    SHAPE ABUTMENT ;
    PORT
      LAYER metal2 ;
      RECT 86.605 0.000 86.675 0.210 ;
    END
  END w0_wd_in[178]
  PIN w0_wd_in[179]
    DIRECTION OUTPUT ;
    USE SIGNAL ;
    SHAPE ABUTMENT ;
    PORT
      LAYER metal2 ;
      RECT 88.315 0.000 88.385 0.210 ;
    END
  END w0_wd_in[179]
  PIN w0_wd_in[180]
    DIRECTION OUTPUT ;
    USE SIGNAL ;
    SHAPE ABUTMENT ;
    PORT
      LAYER metal2 ;
      RECT 90.025 0.000 90.095 0.210 ;
    END
  END w0_wd_in[180]
  PIN w0_wd_in[181]
    DIRECTION OUTPUT ;
    USE SIGNAL ;
    SHAPE ABUTMENT ;
    PORT
      LAYER metal2 ;
      RECT 91.735 0.000 91.805 0.210 ;
    END
  END w0_wd_in[181]
  PIN w0_wd_in[182]
    DIRECTION OUTPUT ;
    USE SIGNAL ;
    SHAPE ABUTMENT ;
    PORT
      LAYER metal2 ;
      RECT 93.445 0.000 93.515 0.210 ;
    END
  END w0_wd_in[182]
  PIN w0_wd_in[183]
    DIRECTION OUTPUT ;
    USE SIGNAL ;
    SHAPE ABUTMENT ;
    PORT
      LAYER metal2 ;
      RECT 95.155 0.000 95.225 0.210 ;
    END
  END w0_wd_in[183]
  PIN w0_wd_in[184]
    DIRECTION OUTPUT ;
    USE SIGNAL ;
    SHAPE ABUTMENT ;
    PORT
      LAYER metal2 ;
      RECT 96.865 0.000 96.935 0.210 ;
    END
  END w0_wd_in[184]
  PIN w0_wd_in[185]
    DIRECTION OUTPUT ;
    USE SIGNAL ;
    SHAPE ABUTMENT ;
    PORT
      LAYER metal2 ;
      RECT 98.575 0.000 98.645 0.210 ;
    END
  END w0_wd_in[185]
  PIN w0_wd_in[186]
    DIRECTION OUTPUT ;
    USE SIGNAL ;
    SHAPE ABUTMENT ;
    PORT
      LAYER metal2 ;
      RECT 100.285 0.000 100.355 0.210 ;
    END
  END w0_wd_in[186]
  PIN w0_wd_in[187]
    DIRECTION OUTPUT ;
    USE SIGNAL ;
    SHAPE ABUTMENT ;
    PORT
      LAYER metal2 ;
      RECT 101.995 0.000 102.065 0.210 ;
    END
  END w0_wd_in[187]
  PIN w0_wd_in[188]
    DIRECTION OUTPUT ;
    USE SIGNAL ;
    SHAPE ABUTMENT ;
    PORT
      LAYER metal2 ;
      RECT 103.705 0.000 103.775 0.210 ;
    END
  END w0_wd_in[188]
  PIN w0_wd_in[189]
    DIRECTION OUTPUT ;
    USE SIGNAL ;
    SHAPE ABUTMENT ;
    PORT
      LAYER metal2 ;
      RECT 105.415 0.000 105.485 0.210 ;
    END
  END w0_wd_in[189]
  PIN w0_wd_in[190]
    DIRECTION OUTPUT ;
    USE SIGNAL ;
    SHAPE ABUTMENT ;
    PORT
      LAYER metal2 ;
      RECT 107.125 0.000 107.195 0.210 ;
    END
  END w0_wd_in[190]
  PIN w0_wd_in[191]
    DIRECTION OUTPUT ;
    USE SIGNAL ;
    SHAPE ABUTMENT ;
    PORT
      LAYER metal2 ;
      RECT 108.835 0.000 108.905 0.210 ;
    END
  END w0_wd_in[191]
  PIN w0_wd_in[192]
    DIRECTION OUTPUT ;
    USE SIGNAL ;
    SHAPE ABUTMENT ;
    PORT
      LAYER metal2 ;
      RECT 110.545 0.000 110.615 0.210 ;
    END
  END w0_wd_in[192]
  PIN w0_wd_in[193]
    DIRECTION OUTPUT ;
    USE SIGNAL ;
    SHAPE ABUTMENT ;
    PORT
      LAYER metal2 ;
      RECT 112.255 0.000 112.325 0.210 ;
    END
  END w0_wd_in[193]
  PIN w0_wd_in[194]
    DIRECTION OUTPUT ;
    USE SIGNAL ;
    SHAPE ABUTMENT ;
    PORT
      LAYER metal2 ;
      RECT 113.965 0.000 114.035 0.210 ;
    END
  END w0_wd_in[194]
  PIN w0_wd_in[195]
    DIRECTION OUTPUT ;
    USE SIGNAL ;
    SHAPE ABUTMENT ;
    PORT
      LAYER metal2 ;
      RECT 115.675 0.000 115.745 0.210 ;
    END
  END w0_wd_in[195]
  PIN w0_wd_in[196]
    DIRECTION OUTPUT ;
    USE SIGNAL ;
    SHAPE ABUTMENT ;
    PORT
      LAYER metal2 ;
      RECT 117.385 0.000 117.455 0.210 ;
    END
  END w0_wd_in[196]
  PIN w0_wd_in[197]
    DIRECTION OUTPUT ;
    USE SIGNAL ;
    SHAPE ABUTMENT ;
    PORT
      LAYER metal2 ;
      RECT 119.095 0.000 119.165 0.210 ;
    END
  END w0_wd_in[197]
  PIN w0_wd_in[198]
    DIRECTION OUTPUT ;
    USE SIGNAL ;
    SHAPE ABUTMENT ;
    PORT
      LAYER metal2 ;
      RECT 120.805 0.000 120.875 0.210 ;
    END
  END w0_wd_in[198]
  PIN w0_wd_in[199]
    DIRECTION OUTPUT ;
    USE SIGNAL ;
    SHAPE ABUTMENT ;
    PORT
      LAYER metal2 ;
      RECT 122.515 0.000 122.585 0.210 ;
    END
  END w0_wd_in[199]
  PIN w0_wd_in[200]
    DIRECTION OUTPUT ;
    USE SIGNAL ;
    SHAPE ABUTMENT ;
    PORT
      LAYER metal2 ;
      RECT 124.225 0.000 124.295 0.210 ;
    END
  END w0_wd_in[200]
  PIN w0_wd_in[201]
    DIRECTION OUTPUT ;
    USE SIGNAL ;
    SHAPE ABUTMENT ;
    PORT
      LAYER metal2 ;
      RECT 125.935 0.000 126.005 0.210 ;
    END
  END w0_wd_in[201]
  PIN w0_wd_in[202]
    DIRECTION OUTPUT ;
    USE SIGNAL ;
    SHAPE ABUTMENT ;
    PORT
      LAYER metal2 ;
      RECT 127.645 0.000 127.715 0.210 ;
    END
  END w0_wd_in[202]
  PIN w0_wd_in[203]
    DIRECTION OUTPUT ;
    USE SIGNAL ;
    SHAPE ABUTMENT ;
    PORT
      LAYER metal2 ;
      RECT 129.355 0.000 129.425 0.210 ;
    END
  END w0_wd_in[203]
  PIN w0_wd_in[204]
    DIRECTION OUTPUT ;
    USE SIGNAL ;
    SHAPE ABUTMENT ;
    PORT
      LAYER metal2 ;
      RECT 131.065 0.000 131.135 0.210 ;
    END
  END w0_wd_in[204]
  PIN w0_wd_in[205]
    DIRECTION OUTPUT ;
    USE SIGNAL ;
    SHAPE ABUTMENT ;
    PORT
      LAYER metal2 ;
      RECT 132.775 0.000 132.845 0.210 ;
    END
  END w0_wd_in[205]
  PIN w0_wd_in[206]
    DIRECTION OUTPUT ;
    USE SIGNAL ;
    SHAPE ABUTMENT ;
    PORT
      LAYER metal2 ;
      RECT 134.485 0.000 134.555 0.210 ;
    END
  END w0_wd_in[206]
  PIN w0_wd_in[207]
    DIRECTION OUTPUT ;
    USE SIGNAL ;
    SHAPE ABUTMENT ;
    PORT
      LAYER metal2 ;
      RECT 136.195 0.000 136.265 0.210 ;
    END
  END w0_wd_in[207]
  PIN w0_wd_in[208]
    DIRECTION OUTPUT ;
    USE SIGNAL ;
    SHAPE ABUTMENT ;
    PORT
      LAYER metal2 ;
      RECT 137.905 0.000 137.975 0.210 ;
    END
  END w0_wd_in[208]
  PIN w0_wd_in[209]
    DIRECTION OUTPUT ;
    USE SIGNAL ;
    SHAPE ABUTMENT ;
    PORT
      LAYER metal2 ;
      RECT 139.615 0.000 139.685 0.210 ;
    END
  END w0_wd_in[209]
  PIN w0_wd_in[210]
    DIRECTION OUTPUT ;
    USE SIGNAL ;
    SHAPE ABUTMENT ;
    PORT
      LAYER metal2 ;
      RECT 141.325 0.000 141.395 0.210 ;
    END
  END w0_wd_in[210]
  PIN w0_wd_in[211]
    DIRECTION OUTPUT ;
    USE SIGNAL ;
    SHAPE ABUTMENT ;
    PORT
      LAYER metal2 ;
      RECT 143.035 0.000 143.105 0.210 ;
    END
  END w0_wd_in[211]
  PIN w0_wd_in[212]
    DIRECTION OUTPUT ;
    USE SIGNAL ;
    SHAPE ABUTMENT ;
    PORT
      LAYER metal2 ;
      RECT 144.745 0.000 144.815 0.210 ;
    END
  END w0_wd_in[212]
  PIN w0_wd_in[213]
    DIRECTION OUTPUT ;
    USE SIGNAL ;
    SHAPE ABUTMENT ;
    PORT
      LAYER metal2 ;
      RECT 146.455 0.000 146.525 0.210 ;
    END
  END w0_wd_in[213]
  PIN w0_wd_in[214]
    DIRECTION OUTPUT ;
    USE SIGNAL ;
    SHAPE ABUTMENT ;
    PORT
      LAYER metal2 ;
      RECT 148.165 0.000 148.235 0.210 ;
    END
  END w0_wd_in[214]
  PIN w0_wd_in[215]
    DIRECTION OUTPUT ;
    USE SIGNAL ;
    SHAPE ABUTMENT ;
    PORT
      LAYER metal2 ;
      RECT 149.875 0.000 149.945 0.210 ;
    END
  END w0_wd_in[215]
  PIN w0_wd_in[216]
    DIRECTION OUTPUT ;
    USE SIGNAL ;
    SHAPE ABUTMENT ;
    PORT
      LAYER metal2 ;
      RECT 151.585 0.000 151.655 0.210 ;
    END
  END w0_wd_in[216]
  PIN w0_wd_in[217]
    DIRECTION OUTPUT ;
    USE SIGNAL ;
    SHAPE ABUTMENT ;
    PORT
      LAYER metal2 ;
      RECT 153.295 0.000 153.365 0.210 ;
    END
  END w0_wd_in[217]
  PIN w0_wd_in[218]
    DIRECTION OUTPUT ;
    USE SIGNAL ;
    SHAPE ABUTMENT ;
    PORT
      LAYER metal2 ;
      RECT 155.005 0.000 155.075 0.210 ;
    END
  END w0_wd_in[218]
  PIN w0_wd_in[219]
    DIRECTION OUTPUT ;
    USE SIGNAL ;
    SHAPE ABUTMENT ;
    PORT
      LAYER metal2 ;
      RECT 156.715 0.000 156.785 0.210 ;
    END
  END w0_wd_in[219]
  PIN w0_wd_in[220]
    DIRECTION OUTPUT ;
    USE SIGNAL ;
    SHAPE ABUTMENT ;
    PORT
      LAYER metal2 ;
      RECT 158.425 0.000 158.495 0.210 ;
    END
  END w0_wd_in[220]
  PIN w0_wd_in[221]
    DIRECTION OUTPUT ;
    USE SIGNAL ;
    SHAPE ABUTMENT ;
    PORT
      LAYER metal2 ;
      RECT 160.135 0.000 160.205 0.210 ;
    END
  END w0_wd_in[221]
  PIN w0_wd_in[222]
    DIRECTION OUTPUT ;
    USE SIGNAL ;
    SHAPE ABUTMENT ;
    PORT
      LAYER metal2 ;
      RECT 161.845 0.000 161.915 0.210 ;
    END
  END w0_wd_in[222]
  PIN w0_wd_in[223]
    DIRECTION OUTPUT ;
    USE SIGNAL ;
    SHAPE ABUTMENT ;
    PORT
      LAYER metal2 ;
      RECT 163.555 0.000 163.625 0.210 ;
    END
  END w0_wd_in[223]
  PIN w0_wd_in[224]
    DIRECTION OUTPUT ;
    USE SIGNAL ;
    SHAPE ABUTMENT ;
    PORT
      LAYER metal2 ;
      RECT 165.265 0.000 165.335 0.210 ;
    END
  END w0_wd_in[224]
  PIN w0_wd_in[225]
    DIRECTION OUTPUT ;
    USE SIGNAL ;
    SHAPE ABUTMENT ;
    PORT
      LAYER metal2 ;
      RECT 166.975 0.000 167.045 0.210 ;
    END
  END w0_wd_in[225]
  PIN w0_wd_in[226]
    DIRECTION OUTPUT ;
    USE SIGNAL ;
    SHAPE ABUTMENT ;
    PORT
      LAYER metal2 ;
      RECT 168.685 0.000 168.755 0.210 ;
    END
  END w0_wd_in[226]
  PIN w0_wd_in[227]
    DIRECTION OUTPUT ;
    USE SIGNAL ;
    SHAPE ABUTMENT ;
    PORT
      LAYER metal2 ;
      RECT 170.395 0.000 170.465 0.210 ;
    END
  END w0_wd_in[227]
  PIN w0_wd_in[228]
    DIRECTION OUTPUT ;
    USE SIGNAL ;
    SHAPE ABUTMENT ;
    PORT
      LAYER metal2 ;
      RECT 172.105 0.000 172.175 0.210 ;
    END
  END w0_wd_in[228]
  PIN w0_wd_in[229]
    DIRECTION OUTPUT ;
    USE SIGNAL ;
    SHAPE ABUTMENT ;
    PORT
      LAYER metal2 ;
      RECT 173.815 0.000 173.885 0.210 ;
    END
  END w0_wd_in[229]
  PIN w0_wd_in[230]
    DIRECTION OUTPUT ;
    USE SIGNAL ;
    SHAPE ABUTMENT ;
    PORT
      LAYER metal2 ;
      RECT 175.525 0.000 175.595 0.210 ;
    END
  END w0_wd_in[230]
  PIN w0_wd_in[231]
    DIRECTION OUTPUT ;
    USE SIGNAL ;
    SHAPE ABUTMENT ;
    PORT
      LAYER metal2 ;
      RECT 177.235 0.000 177.305 0.210 ;
    END
  END w0_wd_in[231]
  PIN w0_wd_in[232]
    DIRECTION OUTPUT ;
    USE SIGNAL ;
    SHAPE ABUTMENT ;
    PORT
      LAYER metal2 ;
      RECT 178.945 0.000 179.015 0.210 ;
    END
  END w0_wd_in[232]
  PIN w0_wd_in[233]
    DIRECTION OUTPUT ;
    USE SIGNAL ;
    SHAPE ABUTMENT ;
    PORT
      LAYER metal2 ;
      RECT 180.655 0.000 180.725 0.210 ;
    END
  END w0_wd_in[233]
  PIN w0_wd_in[234]
    DIRECTION OUTPUT ;
    USE SIGNAL ;
    SHAPE ABUTMENT ;
    PORT
      LAYER metal2 ;
      RECT 182.365 0.000 182.435 0.210 ;
    END
  END w0_wd_in[234]
  PIN w0_wd_in[235]
    DIRECTION OUTPUT ;
    USE SIGNAL ;
    SHAPE ABUTMENT ;
    PORT
      LAYER metal2 ;
      RECT 184.075 0.000 184.145 0.210 ;
    END
  END w0_wd_in[235]
  PIN w0_wd_in[236]
    DIRECTION OUTPUT ;
    USE SIGNAL ;
    SHAPE ABUTMENT ;
    PORT
      LAYER metal2 ;
      RECT 185.785 0.000 185.855 0.210 ;
    END
  END w0_wd_in[236]
  PIN w0_wd_in[237]
    DIRECTION OUTPUT ;
    USE SIGNAL ;
    SHAPE ABUTMENT ;
    PORT
      LAYER metal2 ;
      RECT 187.495 0.000 187.565 0.210 ;
    END
  END w0_wd_in[237]
  PIN w0_wd_in[238]
    DIRECTION OUTPUT ;
    USE SIGNAL ;
    SHAPE ABUTMENT ;
    PORT
      LAYER metal2 ;
      RECT 189.205 0.000 189.275 0.210 ;
    END
  END w0_wd_in[238]
  PIN w0_wd_in[239]
    DIRECTION OUTPUT ;
    USE SIGNAL ;
    SHAPE ABUTMENT ;
    PORT
      LAYER metal2 ;
      RECT 190.915 0.000 190.985 0.210 ;
    END
  END w0_wd_in[239]
  PIN w0_wd_in[240]
    DIRECTION OUTPUT ;
    USE SIGNAL ;
    SHAPE ABUTMENT ;
    PORT
      LAYER metal2 ;
      RECT 192.625 0.000 192.695 0.210 ;
    END
  END w0_wd_in[240]
  PIN w0_wd_in[241]
    DIRECTION OUTPUT ;
    USE SIGNAL ;
    SHAPE ABUTMENT ;
    PORT
      LAYER metal2 ;
      RECT 194.335 0.000 194.405 0.210 ;
    END
  END w0_wd_in[241]
  PIN w0_wd_in[242]
    DIRECTION OUTPUT ;
    USE SIGNAL ;
    SHAPE ABUTMENT ;
    PORT
      LAYER metal2 ;
      RECT 196.045 0.000 196.115 0.210 ;
    END
  END w0_wd_in[242]
  PIN w0_wd_in[243]
    DIRECTION OUTPUT ;
    USE SIGNAL ;
    SHAPE ABUTMENT ;
    PORT
      LAYER metal2 ;
      RECT 197.755 0.000 197.825 0.210 ;
    END
  END w0_wd_in[243]
  PIN w0_wd_in[244]
    DIRECTION OUTPUT ;
    USE SIGNAL ;
    SHAPE ABUTMENT ;
    PORT
      LAYER metal2 ;
      RECT 199.465 0.000 199.535 0.210 ;
    END
  END w0_wd_in[244]
  PIN w0_wd_in[245]
    DIRECTION OUTPUT ;
    USE SIGNAL ;
    SHAPE ABUTMENT ;
    PORT
      LAYER metal2 ;
      RECT 201.175 0.000 201.245 0.210 ;
    END
  END w0_wd_in[245]
  PIN w0_wd_in[246]
    DIRECTION OUTPUT ;
    USE SIGNAL ;
    SHAPE ABUTMENT ;
    PORT
      LAYER metal2 ;
      RECT 202.885 0.000 202.955 0.210 ;
    END
  END w0_wd_in[246]
  PIN w0_wd_in[247]
    DIRECTION OUTPUT ;
    USE SIGNAL ;
    SHAPE ABUTMENT ;
    PORT
      LAYER metal2 ;
      RECT 204.595 0.000 204.665 0.210 ;
    END
  END w0_wd_in[247]
  PIN w0_wd_in[248]
    DIRECTION OUTPUT ;
    USE SIGNAL ;
    SHAPE ABUTMENT ;
    PORT
      LAYER metal2 ;
      RECT 206.305 0.000 206.375 0.210 ;
    END
  END w0_wd_in[248]
  PIN w0_wd_in[249]
    DIRECTION OUTPUT ;
    USE SIGNAL ;
    SHAPE ABUTMENT ;
    PORT
      LAYER metal2 ;
      RECT 208.015 0.000 208.085 0.210 ;
    END
  END w0_wd_in[249]
  PIN w0_wd_in[250]
    DIRECTION OUTPUT ;
    USE SIGNAL ;
    SHAPE ABUTMENT ;
    PORT
      LAYER metal2 ;
      RECT 209.725 0.000 209.795 0.210 ;
    END
  END w0_wd_in[250]
  PIN w0_wd_in[251]
    DIRECTION OUTPUT ;
    USE SIGNAL ;
    SHAPE ABUTMENT ;
    PORT
      LAYER metal2 ;
      RECT 211.435 0.000 211.505 0.210 ;
    END
  END w0_wd_in[251]
  PIN w0_wd_in[252]
    DIRECTION OUTPUT ;
    USE SIGNAL ;
    SHAPE ABUTMENT ;
    PORT
      LAYER metal2 ;
      RECT 213.145 0.000 213.215 0.210 ;
    END
  END w0_wd_in[252]
  PIN w0_wd_in[253]
    DIRECTION OUTPUT ;
    USE SIGNAL ;
    SHAPE ABUTMENT ;
    PORT
      LAYER metal2 ;
      RECT 214.855 0.000 214.925 0.210 ;
    END
  END w0_wd_in[253]
  PIN w0_wd_in[254]
    DIRECTION OUTPUT ;
    USE SIGNAL ;
    SHAPE ABUTMENT ;
    PORT
      LAYER metal2 ;
      RECT 216.565 0.000 216.635 0.210 ;
    END
  END w0_wd_in[254]
  PIN w0_wd_in[255]
    DIRECTION OUTPUT ;
    USE SIGNAL ;
    SHAPE ABUTMENT ;
    PORT
      LAYER metal2 ;
      RECT 218.275 0.000 218.345 0.210 ;
    END
  END w0_wd_in[255]
  PIN r0_rd_out[0]
    DIRECTION OUTPUT ;
    USE SIGNAL ;
    SHAPE ABUTMENT ;
    PORT
      LAYER metal2 ;
      RECT 219.985 0.000 220.055 0.210 ;
    END
  END r0_rd_out[0]
  PIN r0_rd_out[1]
    DIRECTION OUTPUT ;
    USE SIGNAL ;
    SHAPE ABUTMENT ;
    PORT
      LAYER metal2 ;
      RECT 221.695 0.000 221.765 0.210 ;
    END
  END r0_rd_out[1]
  PIN r0_rd_out[2]
    DIRECTION OUTPUT ;
    USE SIGNAL ;
    SHAPE ABUTMENT ;
    PORT
      LAYER metal2 ;
      RECT 223.405 0.000 223.475 0.210 ;
    END
  END r0_rd_out[2]
  PIN r0_rd_out[3]
    DIRECTION OUTPUT ;
    USE SIGNAL ;
    SHAPE ABUTMENT ;
    PORT
      LAYER metal2 ;
      RECT 225.115 0.000 225.185 0.210 ;
    END
  END r0_rd_out[3]
  PIN r0_rd_out[4]
    DIRECTION OUTPUT ;
    USE SIGNAL ;
    SHAPE ABUTMENT ;
    PORT
      LAYER metal2 ;
      RECT 226.825 0.000 226.895 0.210 ;
    END
  END r0_rd_out[4]
  PIN r0_rd_out[5]
    DIRECTION OUTPUT ;
    USE SIGNAL ;
    SHAPE ABUTMENT ;
    PORT
      LAYER metal2 ;
      RECT 228.535 0.000 228.605 0.210 ;
    END
  END r0_rd_out[5]
  PIN r0_rd_out[6]
    DIRECTION OUTPUT ;
    USE SIGNAL ;
    SHAPE ABUTMENT ;
    PORT
      LAYER metal2 ;
      RECT 230.245 0.000 230.315 0.210 ;
    END
  END r0_rd_out[6]
  PIN r0_rd_out[7]
    DIRECTION OUTPUT ;
    USE SIGNAL ;
    SHAPE ABUTMENT ;
    PORT
      LAYER metal2 ;
      RECT 231.955 0.000 232.025 0.210 ;
    END
  END r0_rd_out[7]
  PIN r0_rd_out[8]
    DIRECTION OUTPUT ;
    USE SIGNAL ;
    SHAPE ABUTMENT ;
    PORT
      LAYER metal2 ;
      RECT 233.665 0.000 233.735 0.210 ;
    END
  END r0_rd_out[8]
  PIN r0_rd_out[9]
    DIRECTION OUTPUT ;
    USE SIGNAL ;
    SHAPE ABUTMENT ;
    PORT
      LAYER metal2 ;
      RECT 235.375 0.000 235.445 0.210 ;
    END
  END r0_rd_out[9]
  PIN r0_rd_out[10]
    DIRECTION OUTPUT ;
    USE SIGNAL ;
    SHAPE ABUTMENT ;
    PORT
      LAYER metal2 ;
      RECT 237.085 0.000 237.155 0.210 ;
    END
  END r0_rd_out[10]
  PIN r0_rd_out[11]
    DIRECTION OUTPUT ;
    USE SIGNAL ;
    SHAPE ABUTMENT ;
    PORT
      LAYER metal2 ;
      RECT 238.795 0.000 238.865 0.210 ;
    END
  END r0_rd_out[11]
  PIN r0_rd_out[12]
    DIRECTION OUTPUT ;
    USE SIGNAL ;
    SHAPE ABUTMENT ;
    PORT
      LAYER metal2 ;
      RECT 240.505 0.000 240.575 0.210 ;
    END
  END r0_rd_out[12]
  PIN r0_rd_out[13]
    DIRECTION OUTPUT ;
    USE SIGNAL ;
    SHAPE ABUTMENT ;
    PORT
      LAYER metal2 ;
      RECT 242.215 0.000 242.285 0.210 ;
    END
  END r0_rd_out[13]
  PIN r0_rd_out[14]
    DIRECTION OUTPUT ;
    USE SIGNAL ;
    SHAPE ABUTMENT ;
    PORT
      LAYER metal2 ;
      RECT 243.925 0.000 243.995 0.210 ;
    END
  END r0_rd_out[14]
  PIN r0_rd_out[15]
    DIRECTION OUTPUT ;
    USE SIGNAL ;
    SHAPE ABUTMENT ;
    PORT
      LAYER metal2 ;
      RECT 245.635 0.000 245.705 0.210 ;
    END
  END r0_rd_out[15]
  PIN r0_rd_out[16]
    DIRECTION OUTPUT ;
    USE SIGNAL ;
    SHAPE ABUTMENT ;
    PORT
      LAYER metal2 ;
      RECT 247.345 0.000 247.415 0.210 ;
    END
  END r0_rd_out[16]
  PIN r0_rd_out[17]
    DIRECTION OUTPUT ;
    USE SIGNAL ;
    SHAPE ABUTMENT ;
    PORT
      LAYER metal2 ;
      RECT 249.055 0.000 249.125 0.210 ;
    END
  END r0_rd_out[17]
  PIN r0_rd_out[18]
    DIRECTION OUTPUT ;
    USE SIGNAL ;
    SHAPE ABUTMENT ;
    PORT
      LAYER metal2 ;
      RECT 250.765 0.000 250.835 0.210 ;
    END
  END r0_rd_out[18]
  PIN r0_rd_out[19]
    DIRECTION OUTPUT ;
    USE SIGNAL ;
    SHAPE ABUTMENT ;
    PORT
      LAYER metal2 ;
      RECT 252.475 0.000 252.545 0.210 ;
    END
  END r0_rd_out[19]
  PIN r0_rd_out[20]
    DIRECTION OUTPUT ;
    USE SIGNAL ;
    SHAPE ABUTMENT ;
    PORT
      LAYER metal2 ;
      RECT 254.185 0.000 254.255 0.210 ;
    END
  END r0_rd_out[20]
  PIN r0_rd_out[21]
    DIRECTION OUTPUT ;
    USE SIGNAL ;
    SHAPE ABUTMENT ;
    PORT
      LAYER metal2 ;
      RECT 255.895 0.000 255.965 0.210 ;
    END
  END r0_rd_out[21]
  PIN r0_rd_out[22]
    DIRECTION OUTPUT ;
    USE SIGNAL ;
    SHAPE ABUTMENT ;
    PORT
      LAYER metal2 ;
      RECT 257.605 0.000 257.675 0.210 ;
    END
  END r0_rd_out[22]
  PIN r0_rd_out[23]
    DIRECTION OUTPUT ;
    USE SIGNAL ;
    SHAPE ABUTMENT ;
    PORT
      LAYER metal2 ;
      RECT 259.315 0.000 259.385 0.210 ;
    END
  END r0_rd_out[23]
  PIN r0_rd_out[24]
    DIRECTION OUTPUT ;
    USE SIGNAL ;
    SHAPE ABUTMENT ;
    PORT
      LAYER metal2 ;
      RECT 261.025 0.000 261.095 0.210 ;
    END
  END r0_rd_out[24]
  PIN r0_rd_out[25]
    DIRECTION OUTPUT ;
    USE SIGNAL ;
    SHAPE ABUTMENT ;
    PORT
      LAYER metal2 ;
      RECT 262.735 0.000 262.805 0.210 ;
    END
  END r0_rd_out[25]
  PIN r0_rd_out[26]
    DIRECTION OUTPUT ;
    USE SIGNAL ;
    SHAPE ABUTMENT ;
    PORT
      LAYER metal2 ;
      RECT 264.445 0.000 264.515 0.210 ;
    END
  END r0_rd_out[26]
  PIN r0_rd_out[27]
    DIRECTION OUTPUT ;
    USE SIGNAL ;
    SHAPE ABUTMENT ;
    PORT
      LAYER metal2 ;
      RECT 266.155 0.000 266.225 0.210 ;
    END
  END r0_rd_out[27]
  PIN r0_rd_out[28]
    DIRECTION OUTPUT ;
    USE SIGNAL ;
    SHAPE ABUTMENT ;
    PORT
      LAYER metal2 ;
      RECT 267.865 0.000 267.935 0.210 ;
    END
  END r0_rd_out[28]
  PIN r0_rd_out[29]
    DIRECTION OUTPUT ;
    USE SIGNAL ;
    SHAPE ABUTMENT ;
    PORT
      LAYER metal2 ;
      RECT 269.575 0.000 269.645 0.210 ;
    END
  END r0_rd_out[29]
  PIN r0_rd_out[30]
    DIRECTION OUTPUT ;
    USE SIGNAL ;
    SHAPE ABUTMENT ;
    PORT
      LAYER metal2 ;
      RECT 271.285 0.000 271.355 0.210 ;
    END
  END r0_rd_out[30]
  PIN r0_rd_out[31]
    DIRECTION OUTPUT ;
    USE SIGNAL ;
    SHAPE ABUTMENT ;
    PORT
      LAYER metal2 ;
      RECT 272.995 0.000 273.065 0.210 ;
    END
  END r0_rd_out[31]
  PIN r0_rd_out[32]
    DIRECTION OUTPUT ;
    USE SIGNAL ;
    SHAPE ABUTMENT ;
    PORT
      LAYER metal2 ;
      RECT 274.705 0.000 274.775 0.210 ;
    END
  END r0_rd_out[32]
  PIN r0_rd_out[33]
    DIRECTION OUTPUT ;
    USE SIGNAL ;
    SHAPE ABUTMENT ;
    PORT
      LAYER metal2 ;
      RECT 276.415 0.000 276.485 0.210 ;
    END
  END r0_rd_out[33]
  PIN r0_rd_out[34]
    DIRECTION OUTPUT ;
    USE SIGNAL ;
    SHAPE ABUTMENT ;
    PORT
      LAYER metal2 ;
      RECT 278.125 0.000 278.195 0.210 ;
    END
  END r0_rd_out[34]
  PIN r0_rd_out[35]
    DIRECTION OUTPUT ;
    USE SIGNAL ;
    SHAPE ABUTMENT ;
    PORT
      LAYER metal2 ;
      RECT 279.835 0.000 279.905 0.210 ;
    END
  END r0_rd_out[35]
  PIN r0_rd_out[36]
    DIRECTION OUTPUT ;
    USE SIGNAL ;
    SHAPE ABUTMENT ;
    PORT
      LAYER metal2 ;
      RECT 281.545 0.000 281.615 0.210 ;
    END
  END r0_rd_out[36]
  PIN r0_rd_out[37]
    DIRECTION OUTPUT ;
    USE SIGNAL ;
    SHAPE ABUTMENT ;
    PORT
      LAYER metal2 ;
      RECT 283.255 0.000 283.325 0.210 ;
    END
  END r0_rd_out[37]
  PIN r0_rd_out[38]
    DIRECTION OUTPUT ;
    USE SIGNAL ;
    SHAPE ABUTMENT ;
    PORT
      LAYER metal2 ;
      RECT 284.965 0.000 285.035 0.210 ;
    END
  END r0_rd_out[38]
  PIN r0_rd_out[39]
    DIRECTION OUTPUT ;
    USE SIGNAL ;
    SHAPE ABUTMENT ;
    PORT
      LAYER metal2 ;
      RECT 286.675 0.000 286.745 0.210 ;
    END
  END r0_rd_out[39]
  PIN r0_rd_out[40]
    DIRECTION OUTPUT ;
    USE SIGNAL ;
    SHAPE ABUTMENT ;
    PORT
      LAYER metal2 ;
      RECT 288.385 0.000 288.455 0.210 ;
    END
  END r0_rd_out[40]
  PIN r0_rd_out[41]
    DIRECTION OUTPUT ;
    USE SIGNAL ;
    SHAPE ABUTMENT ;
    PORT
      LAYER metal2 ;
      RECT 290.095 0.000 290.165 0.210 ;
    END
  END r0_rd_out[41]
  PIN r0_rd_out[42]
    DIRECTION OUTPUT ;
    USE SIGNAL ;
    SHAPE ABUTMENT ;
    PORT
      LAYER metal2 ;
      RECT 291.805 0.000 291.875 0.210 ;
    END
  END r0_rd_out[42]
  PIN r0_rd_out[43]
    DIRECTION OUTPUT ;
    USE SIGNAL ;
    SHAPE ABUTMENT ;
    PORT
      LAYER metal2 ;
      RECT 293.515 0.000 293.585 0.210 ;
    END
  END r0_rd_out[43]
  PIN r0_rd_out[44]
    DIRECTION OUTPUT ;
    USE SIGNAL ;
    SHAPE ABUTMENT ;
    PORT
      LAYER metal2 ;
      RECT 295.225 0.000 295.295 0.210 ;
    END
  END r0_rd_out[44]
  PIN r0_rd_out[45]
    DIRECTION OUTPUT ;
    USE SIGNAL ;
    SHAPE ABUTMENT ;
    PORT
      LAYER metal2 ;
      RECT 296.935 0.000 297.005 0.210 ;
    END
  END r0_rd_out[45]
  PIN r0_rd_out[46]
    DIRECTION OUTPUT ;
    USE SIGNAL ;
    SHAPE ABUTMENT ;
    PORT
      LAYER metal2 ;
      RECT 298.645 0.000 298.715 0.210 ;
    END
  END r0_rd_out[46]
  PIN r0_rd_out[47]
    DIRECTION OUTPUT ;
    USE SIGNAL ;
    SHAPE ABUTMENT ;
    PORT
      LAYER metal2 ;
      RECT 300.355 0.000 300.425 0.210 ;
    END
  END r0_rd_out[47]
  PIN r0_rd_out[48]
    DIRECTION OUTPUT ;
    USE SIGNAL ;
    SHAPE ABUTMENT ;
    PORT
      LAYER metal2 ;
      RECT 302.065 0.000 302.135 0.210 ;
    END
  END r0_rd_out[48]
  PIN r0_rd_out[49]
    DIRECTION OUTPUT ;
    USE SIGNAL ;
    SHAPE ABUTMENT ;
    PORT
      LAYER metal2 ;
      RECT 303.775 0.000 303.845 0.210 ;
    END
  END r0_rd_out[49]
  PIN r0_rd_out[50]
    DIRECTION OUTPUT ;
    USE SIGNAL ;
    SHAPE ABUTMENT ;
    PORT
      LAYER metal2 ;
      RECT 305.485 0.000 305.555 0.210 ;
    END
  END r0_rd_out[50]
  PIN r0_rd_out[51]
    DIRECTION OUTPUT ;
    USE SIGNAL ;
    SHAPE ABUTMENT ;
    PORT
      LAYER metal2 ;
      RECT 307.195 0.000 307.265 0.210 ;
    END
  END r0_rd_out[51]
  PIN r0_rd_out[52]
    DIRECTION OUTPUT ;
    USE SIGNAL ;
    SHAPE ABUTMENT ;
    PORT
      LAYER metal2 ;
      RECT 308.905 0.000 308.975 0.210 ;
    END
  END r0_rd_out[52]
  PIN r0_rd_out[53]
    DIRECTION OUTPUT ;
    USE SIGNAL ;
    SHAPE ABUTMENT ;
    PORT
      LAYER metal2 ;
      RECT 310.615 0.000 310.685 0.210 ;
    END
  END r0_rd_out[53]
  PIN r0_rd_out[54]
    DIRECTION OUTPUT ;
    USE SIGNAL ;
    SHAPE ABUTMENT ;
    PORT
      LAYER metal2 ;
      RECT 312.325 0.000 312.395 0.210 ;
    END
  END r0_rd_out[54]
  PIN r0_rd_out[55]
    DIRECTION OUTPUT ;
    USE SIGNAL ;
    SHAPE ABUTMENT ;
    PORT
      LAYER metal2 ;
      RECT 314.035 0.000 314.105 0.210 ;
    END
  END r0_rd_out[55]
  PIN r0_rd_out[56]
    DIRECTION OUTPUT ;
    USE SIGNAL ;
    SHAPE ABUTMENT ;
    PORT
      LAYER metal2 ;
      RECT 315.745 0.000 315.815 0.210 ;
    END
  END r0_rd_out[56]
  PIN r0_rd_out[57]
    DIRECTION OUTPUT ;
    USE SIGNAL ;
    SHAPE ABUTMENT ;
    PORT
      LAYER metal2 ;
      RECT 317.455 0.000 317.525 0.210 ;
    END
  END r0_rd_out[57]
  PIN r0_rd_out[58]
    DIRECTION OUTPUT ;
    USE SIGNAL ;
    SHAPE ABUTMENT ;
    PORT
      LAYER metal2 ;
      RECT 319.165 0.000 319.235 0.210 ;
    END
  END r0_rd_out[58]
  PIN r0_rd_out[59]
    DIRECTION OUTPUT ;
    USE SIGNAL ;
    SHAPE ABUTMENT ;
    PORT
      LAYER metal2 ;
      RECT 320.875 0.000 320.945 0.210 ;
    END
  END r0_rd_out[59]
  PIN r0_rd_out[60]
    DIRECTION OUTPUT ;
    USE SIGNAL ;
    SHAPE ABUTMENT ;
    PORT
      LAYER metal2 ;
      RECT 322.585 0.000 322.655 0.210 ;
    END
  END r0_rd_out[60]
  PIN r0_rd_out[61]
    DIRECTION OUTPUT ;
    USE SIGNAL ;
    SHAPE ABUTMENT ;
    PORT
      LAYER metal2 ;
      RECT 324.295 0.000 324.365 0.210 ;
    END
  END r0_rd_out[61]
  PIN r0_rd_out[62]
    DIRECTION OUTPUT ;
    USE SIGNAL ;
    SHAPE ABUTMENT ;
    PORT
      LAYER metal2 ;
      RECT 326.005 0.000 326.075 0.210 ;
    END
  END r0_rd_out[62]
  PIN r0_rd_out[63]
    DIRECTION OUTPUT ;
    USE SIGNAL ;
    SHAPE ABUTMENT ;
    PORT
      LAYER metal2 ;
      RECT 327.715 0.000 327.785 0.210 ;
    END
  END r0_rd_out[63]
  PIN r0_rd_out[64]
    DIRECTION OUTPUT ;
    USE SIGNAL ;
    SHAPE ABUTMENT ;
    PORT
      LAYER metal2 ;
      RECT 329.425 0.000 329.495 0.210 ;
    END
  END r0_rd_out[64]
  PIN r0_rd_out[65]
    DIRECTION OUTPUT ;
    USE SIGNAL ;
    SHAPE ABUTMENT ;
    PORT
      LAYER metal2 ;
      RECT 331.135 0.000 331.205 0.210 ;
    END
  END r0_rd_out[65]
  PIN r0_rd_out[66]
    DIRECTION OUTPUT ;
    USE SIGNAL ;
    SHAPE ABUTMENT ;
    PORT
      LAYER metal2 ;
      RECT 332.845 0.000 332.915 0.210 ;
    END
  END r0_rd_out[66]
  PIN r0_rd_out[67]
    DIRECTION OUTPUT ;
    USE SIGNAL ;
    SHAPE ABUTMENT ;
    PORT
      LAYER metal2 ;
      RECT 334.555 0.000 334.625 0.210 ;
    END
  END r0_rd_out[67]
  PIN r0_rd_out[68]
    DIRECTION OUTPUT ;
    USE SIGNAL ;
    SHAPE ABUTMENT ;
    PORT
      LAYER metal2 ;
      RECT 336.265 0.000 336.335 0.210 ;
    END
  END r0_rd_out[68]
  PIN r0_rd_out[69]
    DIRECTION OUTPUT ;
    USE SIGNAL ;
    SHAPE ABUTMENT ;
    PORT
      LAYER metal2 ;
      RECT 337.975 0.000 338.045 0.210 ;
    END
  END r0_rd_out[69]
  PIN r0_rd_out[70]
    DIRECTION OUTPUT ;
    USE SIGNAL ;
    SHAPE ABUTMENT ;
    PORT
      LAYER metal2 ;
      RECT 339.685 0.000 339.755 0.210 ;
    END
  END r0_rd_out[70]
  PIN r0_rd_out[71]
    DIRECTION OUTPUT ;
    USE SIGNAL ;
    SHAPE ABUTMENT ;
    PORT
      LAYER metal2 ;
      RECT 341.395 0.000 341.465 0.210 ;
    END
  END r0_rd_out[71]
  PIN r0_rd_out[72]
    DIRECTION OUTPUT ;
    USE SIGNAL ;
    SHAPE ABUTMENT ;
    PORT
      LAYER metal2 ;
      RECT 343.105 0.000 343.175 0.210 ;
    END
  END r0_rd_out[72]
  PIN r0_rd_out[73]
    DIRECTION OUTPUT ;
    USE SIGNAL ;
    SHAPE ABUTMENT ;
    PORT
      LAYER metal2 ;
      RECT 344.815 0.000 344.885 0.210 ;
    END
  END r0_rd_out[73]
  PIN r0_rd_out[74]
    DIRECTION OUTPUT ;
    USE SIGNAL ;
    SHAPE ABUTMENT ;
    PORT
      LAYER metal2 ;
      RECT 346.525 0.000 346.595 0.210 ;
    END
  END r0_rd_out[74]
  PIN r0_rd_out[75]
    DIRECTION OUTPUT ;
    USE SIGNAL ;
    SHAPE ABUTMENT ;
    PORT
      LAYER metal2 ;
      RECT 348.235 0.000 348.305 0.210 ;
    END
  END r0_rd_out[75]
  PIN r0_rd_out[76]
    DIRECTION OUTPUT ;
    USE SIGNAL ;
    SHAPE ABUTMENT ;
    PORT
      LAYER metal2 ;
      RECT 349.945 0.000 350.015 0.210 ;
    END
  END r0_rd_out[76]
  PIN r0_rd_out[77]
    DIRECTION OUTPUT ;
    USE SIGNAL ;
    SHAPE ABUTMENT ;
    PORT
      LAYER metal2 ;
      RECT 351.655 0.000 351.725 0.210 ;
    END
  END r0_rd_out[77]
  PIN r0_rd_out[78]
    DIRECTION OUTPUT ;
    USE SIGNAL ;
    SHAPE ABUTMENT ;
    PORT
      LAYER metal2 ;
      RECT 353.365 0.000 353.435 0.210 ;
    END
  END r0_rd_out[78]
  PIN r0_rd_out[79]
    DIRECTION OUTPUT ;
    USE SIGNAL ;
    SHAPE ABUTMENT ;
    PORT
      LAYER metal2 ;
      RECT 355.075 0.000 355.145 0.210 ;
    END
  END r0_rd_out[79]
  PIN r0_rd_out[80]
    DIRECTION OUTPUT ;
    USE SIGNAL ;
    SHAPE ABUTMENT ;
    PORT
      LAYER metal2 ;
      RECT 356.785 0.000 356.855 0.210 ;
    END
  END r0_rd_out[80]
  PIN r0_rd_out[81]
    DIRECTION OUTPUT ;
    USE SIGNAL ;
    SHAPE ABUTMENT ;
    PORT
      LAYER metal2 ;
      RECT 358.495 0.000 358.565 0.210 ;
    END
  END r0_rd_out[81]
  PIN r0_rd_out[82]
    DIRECTION OUTPUT ;
    USE SIGNAL ;
    SHAPE ABUTMENT ;
    PORT
      LAYER metal2 ;
      RECT 360.205 0.000 360.275 0.210 ;
    END
  END r0_rd_out[82]
  PIN r0_rd_out[83]
    DIRECTION OUTPUT ;
    USE SIGNAL ;
    SHAPE ABUTMENT ;
    PORT
      LAYER metal2 ;
      RECT 361.915 0.000 361.985 0.210 ;
    END
  END r0_rd_out[83]
  PIN r0_rd_out[84]
    DIRECTION OUTPUT ;
    USE SIGNAL ;
    SHAPE ABUTMENT ;
    PORT
      LAYER metal2 ;
      RECT 363.625 0.000 363.695 0.210 ;
    END
  END r0_rd_out[84]
  PIN r0_rd_out[85]
    DIRECTION OUTPUT ;
    USE SIGNAL ;
    SHAPE ABUTMENT ;
    PORT
      LAYER metal2 ;
      RECT 365.335 0.000 365.405 0.210 ;
    END
  END r0_rd_out[85]
  PIN r0_rd_out[86]
    DIRECTION OUTPUT ;
    USE SIGNAL ;
    SHAPE ABUTMENT ;
    PORT
      LAYER metal2 ;
      RECT 367.045 0.000 367.115 0.210 ;
    END
  END r0_rd_out[86]
  PIN r0_rd_out[87]
    DIRECTION OUTPUT ;
    USE SIGNAL ;
    SHAPE ABUTMENT ;
    PORT
      LAYER metal2 ;
      RECT 368.755 0.000 368.825 0.210 ;
    END
  END r0_rd_out[87]
  PIN r0_rd_out[88]
    DIRECTION OUTPUT ;
    USE SIGNAL ;
    SHAPE ABUTMENT ;
    PORT
      LAYER metal2 ;
      RECT 370.465 0.000 370.535 0.210 ;
    END
  END r0_rd_out[88]
  PIN r0_rd_out[89]
    DIRECTION OUTPUT ;
    USE SIGNAL ;
    SHAPE ABUTMENT ;
    PORT
      LAYER metal2 ;
      RECT 372.175 0.000 372.245 0.210 ;
    END
  END r0_rd_out[89]
  PIN r0_rd_out[90]
    DIRECTION OUTPUT ;
    USE SIGNAL ;
    SHAPE ABUTMENT ;
    PORT
      LAYER metal2 ;
      RECT 373.885 0.000 373.955 0.210 ;
    END
  END r0_rd_out[90]
  PIN r0_rd_out[91]
    DIRECTION OUTPUT ;
    USE SIGNAL ;
    SHAPE ABUTMENT ;
    PORT
      LAYER metal2 ;
      RECT 375.595 0.000 375.665 0.210 ;
    END
  END r0_rd_out[91]
  PIN r0_rd_out[92]
    DIRECTION OUTPUT ;
    USE SIGNAL ;
    SHAPE ABUTMENT ;
    PORT
      LAYER metal2 ;
      RECT 377.305 0.000 377.375 0.210 ;
    END
  END r0_rd_out[92]
  PIN r0_rd_out[93]
    DIRECTION OUTPUT ;
    USE SIGNAL ;
    SHAPE ABUTMENT ;
    PORT
      LAYER metal2 ;
      RECT 379.015 0.000 379.085 0.210 ;
    END
  END r0_rd_out[93]
  PIN r0_rd_out[94]
    DIRECTION OUTPUT ;
    USE SIGNAL ;
    SHAPE ABUTMENT ;
    PORT
      LAYER metal2 ;
      RECT 380.725 0.000 380.795 0.210 ;
    END
  END r0_rd_out[94]
  PIN r0_rd_out[95]
    DIRECTION OUTPUT ;
    USE SIGNAL ;
    SHAPE ABUTMENT ;
    PORT
      LAYER metal2 ;
      RECT 382.435 0.000 382.505 0.210 ;
    END
  END r0_rd_out[95]
  PIN r0_rd_out[96]
    DIRECTION OUTPUT ;
    USE SIGNAL ;
    SHAPE ABUTMENT ;
    PORT
      LAYER metal2 ;
      RECT 384.145 0.000 384.215 0.210 ;
    END
  END r0_rd_out[96]
  PIN r0_rd_out[97]
    DIRECTION OUTPUT ;
    USE SIGNAL ;
    SHAPE ABUTMENT ;
    PORT
      LAYER metal2 ;
      RECT 385.855 0.000 385.925 0.210 ;
    END
  END r0_rd_out[97]
  PIN r0_rd_out[98]
    DIRECTION OUTPUT ;
    USE SIGNAL ;
    SHAPE ABUTMENT ;
    PORT
      LAYER metal2 ;
      RECT 387.565 0.000 387.635 0.210 ;
    END
  END r0_rd_out[98]
  PIN r0_rd_out[99]
    DIRECTION OUTPUT ;
    USE SIGNAL ;
    SHAPE ABUTMENT ;
    PORT
      LAYER metal2 ;
      RECT 389.275 0.000 389.345 0.210 ;
    END
  END r0_rd_out[99]
  PIN r0_rd_out[100]
    DIRECTION OUTPUT ;
    USE SIGNAL ;
    SHAPE ABUTMENT ;
    PORT
      LAYER metal2 ;
      RECT 390.985 0.000 391.055 0.210 ;
    END
  END r0_rd_out[100]
  PIN r0_rd_out[101]
    DIRECTION OUTPUT ;
    USE SIGNAL ;
    SHAPE ABUTMENT ;
    PORT
      LAYER metal2 ;
      RECT 392.695 0.000 392.765 0.210 ;
    END
  END r0_rd_out[101]
  PIN r0_rd_out[102]
    DIRECTION OUTPUT ;
    USE SIGNAL ;
    SHAPE ABUTMENT ;
    PORT
      LAYER metal2 ;
      RECT 394.405 0.000 394.475 0.210 ;
    END
  END r0_rd_out[102]
  PIN r0_rd_out[103]
    DIRECTION OUTPUT ;
    USE SIGNAL ;
    SHAPE ABUTMENT ;
    PORT
      LAYER metal2 ;
      RECT 396.115 0.000 396.185 0.210 ;
    END
  END r0_rd_out[103]
  PIN r0_rd_out[104]
    DIRECTION OUTPUT ;
    USE SIGNAL ;
    SHAPE ABUTMENT ;
    PORT
      LAYER metal2 ;
      RECT 397.825 0.000 397.895 0.210 ;
    END
  END r0_rd_out[104]
  PIN r0_rd_out[105]
    DIRECTION OUTPUT ;
    USE SIGNAL ;
    SHAPE ABUTMENT ;
    PORT
      LAYER metal2 ;
      RECT 399.535 0.000 399.605 0.210 ;
    END
  END r0_rd_out[105]
  PIN r0_rd_out[106]
    DIRECTION OUTPUT ;
    USE SIGNAL ;
    SHAPE ABUTMENT ;
    PORT
      LAYER metal2 ;
      RECT 401.245 0.000 401.315 0.210 ;
    END
  END r0_rd_out[106]
  PIN r0_rd_out[107]
    DIRECTION OUTPUT ;
    USE SIGNAL ;
    SHAPE ABUTMENT ;
    PORT
      LAYER metal2 ;
      RECT 402.955 0.000 403.025 0.210 ;
    END
  END r0_rd_out[107]
  PIN r0_rd_out[108]
    DIRECTION OUTPUT ;
    USE SIGNAL ;
    SHAPE ABUTMENT ;
    PORT
      LAYER metal2 ;
      RECT 404.665 0.000 404.735 0.210 ;
    END
  END r0_rd_out[108]
  PIN r0_rd_out[109]
    DIRECTION OUTPUT ;
    USE SIGNAL ;
    SHAPE ABUTMENT ;
    PORT
      LAYER metal2 ;
      RECT 406.375 0.000 406.445 0.210 ;
    END
  END r0_rd_out[109]
  PIN r0_rd_out[110]
    DIRECTION OUTPUT ;
    USE SIGNAL ;
    SHAPE ABUTMENT ;
    PORT
      LAYER metal2 ;
      RECT 408.085 0.000 408.155 0.210 ;
    END
  END r0_rd_out[110]
  PIN r0_rd_out[111]
    DIRECTION OUTPUT ;
    USE SIGNAL ;
    SHAPE ABUTMENT ;
    PORT
      LAYER metal2 ;
      RECT 409.795 0.000 409.865 0.210 ;
    END
  END r0_rd_out[111]
  PIN r0_rd_out[112]
    DIRECTION OUTPUT ;
    USE SIGNAL ;
    SHAPE ABUTMENT ;
    PORT
      LAYER metal2 ;
      RECT 411.505 0.000 411.575 0.210 ;
    END
  END r0_rd_out[112]
  PIN r0_rd_out[113]
    DIRECTION OUTPUT ;
    USE SIGNAL ;
    SHAPE ABUTMENT ;
    PORT
      LAYER metal2 ;
      RECT 413.215 0.000 413.285 0.210 ;
    END
  END r0_rd_out[113]
  PIN r0_rd_out[114]
    DIRECTION OUTPUT ;
    USE SIGNAL ;
    SHAPE ABUTMENT ;
    PORT
      LAYER metal2 ;
      RECT 414.925 0.000 414.995 0.210 ;
    END
  END r0_rd_out[114]
  PIN r0_rd_out[115]
    DIRECTION OUTPUT ;
    USE SIGNAL ;
    SHAPE ABUTMENT ;
    PORT
      LAYER metal2 ;
      RECT 416.635 0.000 416.705 0.210 ;
    END
  END r0_rd_out[115]
  PIN r0_rd_out[116]
    DIRECTION OUTPUT ;
    USE SIGNAL ;
    SHAPE ABUTMENT ;
    PORT
      LAYER metal2 ;
      RECT 418.345 0.000 418.415 0.210 ;
    END
  END r0_rd_out[116]
  PIN r0_rd_out[117]
    DIRECTION OUTPUT ;
    USE SIGNAL ;
    SHAPE ABUTMENT ;
    PORT
      LAYER metal2 ;
      RECT 420.055 0.000 420.125 0.210 ;
    END
  END r0_rd_out[117]
  PIN r0_rd_out[118]
    DIRECTION OUTPUT ;
    USE SIGNAL ;
    SHAPE ABUTMENT ;
    PORT
      LAYER metal2 ;
      RECT 421.765 0.000 421.835 0.210 ;
    END
  END r0_rd_out[118]
  PIN r0_rd_out[119]
    DIRECTION OUTPUT ;
    USE SIGNAL ;
    SHAPE ABUTMENT ;
    PORT
      LAYER metal2 ;
      RECT 423.475 0.000 423.545 0.210 ;
    END
  END r0_rd_out[119]
  PIN r0_rd_out[120]
    DIRECTION OUTPUT ;
    USE SIGNAL ;
    SHAPE ABUTMENT ;
    PORT
      LAYER metal2 ;
      RECT 425.185 0.000 425.255 0.210 ;
    END
  END r0_rd_out[120]
  PIN r0_rd_out[121]
    DIRECTION OUTPUT ;
    USE SIGNAL ;
    SHAPE ABUTMENT ;
    PORT
      LAYER metal2 ;
      RECT 426.895 0.000 426.965 0.210 ;
    END
  END r0_rd_out[121]
  PIN r0_rd_out[122]
    DIRECTION OUTPUT ;
    USE SIGNAL ;
    SHAPE ABUTMENT ;
    PORT
      LAYER metal2 ;
      RECT 428.605 0.000 428.675 0.210 ;
    END
  END r0_rd_out[122]
  PIN r0_rd_out[123]
    DIRECTION OUTPUT ;
    USE SIGNAL ;
    SHAPE ABUTMENT ;
    PORT
      LAYER metal2 ;
      RECT 430.315 0.000 430.385 0.210 ;
    END
  END r0_rd_out[123]
  PIN r0_rd_out[124]
    DIRECTION OUTPUT ;
    USE SIGNAL ;
    SHAPE ABUTMENT ;
    PORT
      LAYER metal2 ;
      RECT 432.025 0.000 432.095 0.210 ;
    END
  END r0_rd_out[124]
  PIN r0_rd_out[125]
    DIRECTION OUTPUT ;
    USE SIGNAL ;
    SHAPE ABUTMENT ;
    PORT
      LAYER metal2 ;
      RECT 433.735 0.000 433.805 0.210 ;
    END
  END r0_rd_out[125]
  PIN r0_rd_out[126]
    DIRECTION OUTPUT ;
    USE SIGNAL ;
    SHAPE ABUTMENT ;
    PORT
      LAYER metal2 ;
      RECT 435.445 0.000 435.515 0.210 ;
    END
  END r0_rd_out[126]
  PIN r0_rd_out[127]
    DIRECTION OUTPUT ;
    USE SIGNAL ;
    SHAPE ABUTMENT ;
    PORT
      LAYER metal2 ;
      RECT 437.155 0.000 437.225 0.210 ;
    END
  END r0_rd_out[127]
  PIN r0_rd_out[128]
    DIRECTION OUTPUT ;
    USE SIGNAL ;
    SHAPE ABUTMENT ;
    PORT
      LAYER metal2 ;
      RECT 1.105 460.390 1.175 460.600 ;
    END
  END r0_rd_out[128]
  PIN r0_rd_out[129]
    DIRECTION OUTPUT ;
    USE SIGNAL ;
    SHAPE ABUTMENT ;
    PORT
      LAYER metal2 ;
      RECT 4.525 460.390 4.595 460.600 ;
    END
  END r0_rd_out[129]
  PIN r0_rd_out[130]
    DIRECTION OUTPUT ;
    USE SIGNAL ;
    SHAPE ABUTMENT ;
    PORT
      LAYER metal2 ;
      RECT 7.945 460.390 8.015 460.600 ;
    END
  END r0_rd_out[130]
  PIN r0_rd_out[131]
    DIRECTION OUTPUT ;
    USE SIGNAL ;
    SHAPE ABUTMENT ;
    PORT
      LAYER metal2 ;
      RECT 11.365 460.390 11.435 460.600 ;
    END
  END r0_rd_out[131]
  PIN r0_rd_out[132]
    DIRECTION OUTPUT ;
    USE SIGNAL ;
    SHAPE ABUTMENT ;
    PORT
      LAYER metal2 ;
      RECT 14.785 460.390 14.855 460.600 ;
    END
  END r0_rd_out[132]
  PIN r0_rd_out[133]
    DIRECTION OUTPUT ;
    USE SIGNAL ;
    SHAPE ABUTMENT ;
    PORT
      LAYER metal2 ;
      RECT 18.205 460.390 18.275 460.600 ;
    END
  END r0_rd_out[133]
  PIN r0_rd_out[134]
    DIRECTION OUTPUT ;
    USE SIGNAL ;
    SHAPE ABUTMENT ;
    PORT
      LAYER metal2 ;
      RECT 21.625 460.390 21.695 460.600 ;
    END
  END r0_rd_out[134]
  PIN r0_rd_out[135]
    DIRECTION OUTPUT ;
    USE SIGNAL ;
    SHAPE ABUTMENT ;
    PORT
      LAYER metal2 ;
      RECT 25.045 460.390 25.115 460.600 ;
    END
  END r0_rd_out[135]
  PIN r0_rd_out[136]
    DIRECTION OUTPUT ;
    USE SIGNAL ;
    SHAPE ABUTMENT ;
    PORT
      LAYER metal2 ;
      RECT 28.465 460.390 28.535 460.600 ;
    END
  END r0_rd_out[136]
  PIN r0_rd_out[137]
    DIRECTION OUTPUT ;
    USE SIGNAL ;
    SHAPE ABUTMENT ;
    PORT
      LAYER metal2 ;
      RECT 31.885 460.390 31.955 460.600 ;
    END
  END r0_rd_out[137]
  PIN r0_rd_out[138]
    DIRECTION OUTPUT ;
    USE SIGNAL ;
    SHAPE ABUTMENT ;
    PORT
      LAYER metal2 ;
      RECT 35.305 460.390 35.375 460.600 ;
    END
  END r0_rd_out[138]
  PIN r0_rd_out[139]
    DIRECTION OUTPUT ;
    USE SIGNAL ;
    SHAPE ABUTMENT ;
    PORT
      LAYER metal2 ;
      RECT 38.725 460.390 38.795 460.600 ;
    END
  END r0_rd_out[139]
  PIN r0_rd_out[140]
    DIRECTION OUTPUT ;
    USE SIGNAL ;
    SHAPE ABUTMENT ;
    PORT
      LAYER metal2 ;
      RECT 42.145 460.390 42.215 460.600 ;
    END
  END r0_rd_out[140]
  PIN r0_rd_out[141]
    DIRECTION OUTPUT ;
    USE SIGNAL ;
    SHAPE ABUTMENT ;
    PORT
      LAYER metal2 ;
      RECT 45.565 460.390 45.635 460.600 ;
    END
  END r0_rd_out[141]
  PIN r0_rd_out[142]
    DIRECTION OUTPUT ;
    USE SIGNAL ;
    SHAPE ABUTMENT ;
    PORT
      LAYER metal2 ;
      RECT 48.985 460.390 49.055 460.600 ;
    END
  END r0_rd_out[142]
  PIN r0_rd_out[143]
    DIRECTION OUTPUT ;
    USE SIGNAL ;
    SHAPE ABUTMENT ;
    PORT
      LAYER metal2 ;
      RECT 52.405 460.390 52.475 460.600 ;
    END
  END r0_rd_out[143]
  PIN r0_rd_out[144]
    DIRECTION OUTPUT ;
    USE SIGNAL ;
    SHAPE ABUTMENT ;
    PORT
      LAYER metal2 ;
      RECT 55.825 460.390 55.895 460.600 ;
    END
  END r0_rd_out[144]
  PIN r0_rd_out[145]
    DIRECTION OUTPUT ;
    USE SIGNAL ;
    SHAPE ABUTMENT ;
    PORT
      LAYER metal2 ;
      RECT 59.245 460.390 59.315 460.600 ;
    END
  END r0_rd_out[145]
  PIN r0_rd_out[146]
    DIRECTION OUTPUT ;
    USE SIGNAL ;
    SHAPE ABUTMENT ;
    PORT
      LAYER metal2 ;
      RECT 62.665 460.390 62.735 460.600 ;
    END
  END r0_rd_out[146]
  PIN r0_rd_out[147]
    DIRECTION OUTPUT ;
    USE SIGNAL ;
    SHAPE ABUTMENT ;
    PORT
      LAYER metal2 ;
      RECT 66.085 460.390 66.155 460.600 ;
    END
  END r0_rd_out[147]
  PIN r0_rd_out[148]
    DIRECTION OUTPUT ;
    USE SIGNAL ;
    SHAPE ABUTMENT ;
    PORT
      LAYER metal2 ;
      RECT 69.505 460.390 69.575 460.600 ;
    END
  END r0_rd_out[148]
  PIN r0_rd_out[149]
    DIRECTION OUTPUT ;
    USE SIGNAL ;
    SHAPE ABUTMENT ;
    PORT
      LAYER metal2 ;
      RECT 72.925 460.390 72.995 460.600 ;
    END
  END r0_rd_out[149]
  PIN r0_rd_out[150]
    DIRECTION OUTPUT ;
    USE SIGNAL ;
    SHAPE ABUTMENT ;
    PORT
      LAYER metal2 ;
      RECT 76.345 460.390 76.415 460.600 ;
    END
  END r0_rd_out[150]
  PIN r0_rd_out[151]
    DIRECTION OUTPUT ;
    USE SIGNAL ;
    SHAPE ABUTMENT ;
    PORT
      LAYER metal2 ;
      RECT 79.765 460.390 79.835 460.600 ;
    END
  END r0_rd_out[151]
  PIN r0_rd_out[152]
    DIRECTION OUTPUT ;
    USE SIGNAL ;
    SHAPE ABUTMENT ;
    PORT
      LAYER metal2 ;
      RECT 83.185 460.390 83.255 460.600 ;
    END
  END r0_rd_out[152]
  PIN r0_rd_out[153]
    DIRECTION OUTPUT ;
    USE SIGNAL ;
    SHAPE ABUTMENT ;
    PORT
      LAYER metal2 ;
      RECT 86.605 460.390 86.675 460.600 ;
    END
  END r0_rd_out[153]
  PIN r0_rd_out[154]
    DIRECTION OUTPUT ;
    USE SIGNAL ;
    SHAPE ABUTMENT ;
    PORT
      LAYER metal2 ;
      RECT 90.025 460.390 90.095 460.600 ;
    END
  END r0_rd_out[154]
  PIN r0_rd_out[155]
    DIRECTION OUTPUT ;
    USE SIGNAL ;
    SHAPE ABUTMENT ;
    PORT
      LAYER metal2 ;
      RECT 93.445 460.390 93.515 460.600 ;
    END
  END r0_rd_out[155]
  PIN r0_rd_out[156]
    DIRECTION OUTPUT ;
    USE SIGNAL ;
    SHAPE ABUTMENT ;
    PORT
      LAYER metal2 ;
      RECT 96.865 460.390 96.935 460.600 ;
    END
  END r0_rd_out[156]
  PIN r0_rd_out[157]
    DIRECTION OUTPUT ;
    USE SIGNAL ;
    SHAPE ABUTMENT ;
    PORT
      LAYER metal2 ;
      RECT 100.285 460.390 100.355 460.600 ;
    END
  END r0_rd_out[157]
  PIN r0_rd_out[158]
    DIRECTION OUTPUT ;
    USE SIGNAL ;
    SHAPE ABUTMENT ;
    PORT
      LAYER metal2 ;
      RECT 103.705 460.390 103.775 460.600 ;
    END
  END r0_rd_out[158]
  PIN r0_rd_out[159]
    DIRECTION OUTPUT ;
    USE SIGNAL ;
    SHAPE ABUTMENT ;
    PORT
      LAYER metal2 ;
      RECT 107.125 460.390 107.195 460.600 ;
    END
  END r0_rd_out[159]
  PIN r0_rd_out[160]
    DIRECTION OUTPUT ;
    USE SIGNAL ;
    SHAPE ABUTMENT ;
    PORT
      LAYER metal2 ;
      RECT 110.545 460.390 110.615 460.600 ;
    END
  END r0_rd_out[160]
  PIN r0_rd_out[161]
    DIRECTION OUTPUT ;
    USE SIGNAL ;
    SHAPE ABUTMENT ;
    PORT
      LAYER metal2 ;
      RECT 113.965 460.390 114.035 460.600 ;
    END
  END r0_rd_out[161]
  PIN r0_rd_out[162]
    DIRECTION OUTPUT ;
    USE SIGNAL ;
    SHAPE ABUTMENT ;
    PORT
      LAYER metal2 ;
      RECT 117.385 460.390 117.455 460.600 ;
    END
  END r0_rd_out[162]
  PIN r0_rd_out[163]
    DIRECTION OUTPUT ;
    USE SIGNAL ;
    SHAPE ABUTMENT ;
    PORT
      LAYER metal2 ;
      RECT 120.805 460.390 120.875 460.600 ;
    END
  END r0_rd_out[163]
  PIN r0_rd_out[164]
    DIRECTION OUTPUT ;
    USE SIGNAL ;
    SHAPE ABUTMENT ;
    PORT
      LAYER metal2 ;
      RECT 124.225 460.390 124.295 460.600 ;
    END
  END r0_rd_out[164]
  PIN r0_rd_out[165]
    DIRECTION OUTPUT ;
    USE SIGNAL ;
    SHAPE ABUTMENT ;
    PORT
      LAYER metal2 ;
      RECT 127.645 460.390 127.715 460.600 ;
    END
  END r0_rd_out[165]
  PIN r0_rd_out[166]
    DIRECTION OUTPUT ;
    USE SIGNAL ;
    SHAPE ABUTMENT ;
    PORT
      LAYER metal2 ;
      RECT 131.065 460.390 131.135 460.600 ;
    END
  END r0_rd_out[166]
  PIN r0_rd_out[167]
    DIRECTION OUTPUT ;
    USE SIGNAL ;
    SHAPE ABUTMENT ;
    PORT
      LAYER metal2 ;
      RECT 134.485 460.390 134.555 460.600 ;
    END
  END r0_rd_out[167]
  PIN r0_rd_out[168]
    DIRECTION OUTPUT ;
    USE SIGNAL ;
    SHAPE ABUTMENT ;
    PORT
      LAYER metal2 ;
      RECT 137.905 460.390 137.975 460.600 ;
    END
  END r0_rd_out[168]
  PIN r0_rd_out[169]
    DIRECTION OUTPUT ;
    USE SIGNAL ;
    SHAPE ABUTMENT ;
    PORT
      LAYER metal2 ;
      RECT 141.325 460.390 141.395 460.600 ;
    END
  END r0_rd_out[169]
  PIN r0_rd_out[170]
    DIRECTION OUTPUT ;
    USE SIGNAL ;
    SHAPE ABUTMENT ;
    PORT
      LAYER metal2 ;
      RECT 144.745 460.390 144.815 460.600 ;
    END
  END r0_rd_out[170]
  PIN r0_rd_out[171]
    DIRECTION OUTPUT ;
    USE SIGNAL ;
    SHAPE ABUTMENT ;
    PORT
      LAYER metal2 ;
      RECT 148.165 460.390 148.235 460.600 ;
    END
  END r0_rd_out[171]
  PIN r0_rd_out[172]
    DIRECTION OUTPUT ;
    USE SIGNAL ;
    SHAPE ABUTMENT ;
    PORT
      LAYER metal2 ;
      RECT 151.585 460.390 151.655 460.600 ;
    END
  END r0_rd_out[172]
  PIN r0_rd_out[173]
    DIRECTION OUTPUT ;
    USE SIGNAL ;
    SHAPE ABUTMENT ;
    PORT
      LAYER metal2 ;
      RECT 155.005 460.390 155.075 460.600 ;
    END
  END r0_rd_out[173]
  PIN r0_rd_out[174]
    DIRECTION OUTPUT ;
    USE SIGNAL ;
    SHAPE ABUTMENT ;
    PORT
      LAYER metal2 ;
      RECT 158.425 460.390 158.495 460.600 ;
    END
  END r0_rd_out[174]
  PIN r0_rd_out[175]
    DIRECTION OUTPUT ;
    USE SIGNAL ;
    SHAPE ABUTMENT ;
    PORT
      LAYER metal2 ;
      RECT 161.845 460.390 161.915 460.600 ;
    END
  END r0_rd_out[175]
  PIN r0_rd_out[176]
    DIRECTION OUTPUT ;
    USE SIGNAL ;
    SHAPE ABUTMENT ;
    PORT
      LAYER metal2 ;
      RECT 165.265 460.390 165.335 460.600 ;
    END
  END r0_rd_out[176]
  PIN r0_rd_out[177]
    DIRECTION OUTPUT ;
    USE SIGNAL ;
    SHAPE ABUTMENT ;
    PORT
      LAYER metal2 ;
      RECT 168.685 460.390 168.755 460.600 ;
    END
  END r0_rd_out[177]
  PIN r0_rd_out[178]
    DIRECTION OUTPUT ;
    USE SIGNAL ;
    SHAPE ABUTMENT ;
    PORT
      LAYER metal2 ;
      RECT 172.105 460.390 172.175 460.600 ;
    END
  END r0_rd_out[178]
  PIN r0_rd_out[179]
    DIRECTION OUTPUT ;
    USE SIGNAL ;
    SHAPE ABUTMENT ;
    PORT
      LAYER metal2 ;
      RECT 175.525 460.390 175.595 460.600 ;
    END
  END r0_rd_out[179]
  PIN r0_rd_out[180]
    DIRECTION OUTPUT ;
    USE SIGNAL ;
    SHAPE ABUTMENT ;
    PORT
      LAYER metal2 ;
      RECT 178.945 460.390 179.015 460.600 ;
    END
  END r0_rd_out[180]
  PIN r0_rd_out[181]
    DIRECTION OUTPUT ;
    USE SIGNAL ;
    SHAPE ABUTMENT ;
    PORT
      LAYER metal2 ;
      RECT 182.365 460.390 182.435 460.600 ;
    END
  END r0_rd_out[181]
  PIN r0_rd_out[182]
    DIRECTION OUTPUT ;
    USE SIGNAL ;
    SHAPE ABUTMENT ;
    PORT
      LAYER metal2 ;
      RECT 185.785 460.390 185.855 460.600 ;
    END
  END r0_rd_out[182]
  PIN r0_rd_out[183]
    DIRECTION OUTPUT ;
    USE SIGNAL ;
    SHAPE ABUTMENT ;
    PORT
      LAYER metal2 ;
      RECT 189.205 460.390 189.275 460.600 ;
    END
  END r0_rd_out[183]
  PIN r0_rd_out[184]
    DIRECTION OUTPUT ;
    USE SIGNAL ;
    SHAPE ABUTMENT ;
    PORT
      LAYER metal2 ;
      RECT 192.625 460.390 192.695 460.600 ;
    END
  END r0_rd_out[184]
  PIN r0_rd_out[185]
    DIRECTION OUTPUT ;
    USE SIGNAL ;
    SHAPE ABUTMENT ;
    PORT
      LAYER metal2 ;
      RECT 196.045 460.390 196.115 460.600 ;
    END
  END r0_rd_out[185]
  PIN r0_rd_out[186]
    DIRECTION OUTPUT ;
    USE SIGNAL ;
    SHAPE ABUTMENT ;
    PORT
      LAYER metal2 ;
      RECT 199.465 460.390 199.535 460.600 ;
    END
  END r0_rd_out[186]
  PIN r0_rd_out[187]
    DIRECTION OUTPUT ;
    USE SIGNAL ;
    SHAPE ABUTMENT ;
    PORT
      LAYER metal2 ;
      RECT 202.885 460.390 202.955 460.600 ;
    END
  END r0_rd_out[187]
  PIN r0_rd_out[188]
    DIRECTION OUTPUT ;
    USE SIGNAL ;
    SHAPE ABUTMENT ;
    PORT
      LAYER metal2 ;
      RECT 206.305 460.390 206.375 460.600 ;
    END
  END r0_rd_out[188]
  PIN r0_rd_out[189]
    DIRECTION OUTPUT ;
    USE SIGNAL ;
    SHAPE ABUTMENT ;
    PORT
      LAYER metal2 ;
      RECT 209.725 460.390 209.795 460.600 ;
    END
  END r0_rd_out[189]
  PIN r0_rd_out[190]
    DIRECTION OUTPUT ;
    USE SIGNAL ;
    SHAPE ABUTMENT ;
    PORT
      LAYER metal2 ;
      RECT 213.145 460.390 213.215 460.600 ;
    END
  END r0_rd_out[190]
  PIN r0_rd_out[191]
    DIRECTION OUTPUT ;
    USE SIGNAL ;
    SHAPE ABUTMENT ;
    PORT
      LAYER metal2 ;
      RECT 216.565 460.390 216.635 460.600 ;
    END
  END r0_rd_out[191]
  PIN r0_rd_out[192]
    DIRECTION OUTPUT ;
    USE SIGNAL ;
    SHAPE ABUTMENT ;
    PORT
      LAYER metal2 ;
      RECT 219.985 460.390 220.055 460.600 ;
    END
  END r0_rd_out[192]
  PIN r0_rd_out[193]
    DIRECTION OUTPUT ;
    USE SIGNAL ;
    SHAPE ABUTMENT ;
    PORT
      LAYER metal2 ;
      RECT 223.405 460.390 223.475 460.600 ;
    END
  END r0_rd_out[193]
  PIN r0_rd_out[194]
    DIRECTION OUTPUT ;
    USE SIGNAL ;
    SHAPE ABUTMENT ;
    PORT
      LAYER metal2 ;
      RECT 226.825 460.390 226.895 460.600 ;
    END
  END r0_rd_out[194]
  PIN r0_rd_out[195]
    DIRECTION OUTPUT ;
    USE SIGNAL ;
    SHAPE ABUTMENT ;
    PORT
      LAYER metal2 ;
      RECT 230.245 460.390 230.315 460.600 ;
    END
  END r0_rd_out[195]
  PIN r0_rd_out[196]
    DIRECTION OUTPUT ;
    USE SIGNAL ;
    SHAPE ABUTMENT ;
    PORT
      LAYER metal2 ;
      RECT 233.665 460.390 233.735 460.600 ;
    END
  END r0_rd_out[196]
  PIN r0_rd_out[197]
    DIRECTION OUTPUT ;
    USE SIGNAL ;
    SHAPE ABUTMENT ;
    PORT
      LAYER metal2 ;
      RECT 237.085 460.390 237.155 460.600 ;
    END
  END r0_rd_out[197]
  PIN r0_rd_out[198]
    DIRECTION OUTPUT ;
    USE SIGNAL ;
    SHAPE ABUTMENT ;
    PORT
      LAYER metal2 ;
      RECT 240.505 460.390 240.575 460.600 ;
    END
  END r0_rd_out[198]
  PIN r0_rd_out[199]
    DIRECTION OUTPUT ;
    USE SIGNAL ;
    SHAPE ABUTMENT ;
    PORT
      LAYER metal2 ;
      RECT 243.925 460.390 243.995 460.600 ;
    END
  END r0_rd_out[199]
  PIN r0_rd_out[200]
    DIRECTION OUTPUT ;
    USE SIGNAL ;
    SHAPE ABUTMENT ;
    PORT
      LAYER metal2 ;
      RECT 247.345 460.390 247.415 460.600 ;
    END
  END r0_rd_out[200]
  PIN r0_rd_out[201]
    DIRECTION OUTPUT ;
    USE SIGNAL ;
    SHAPE ABUTMENT ;
    PORT
      LAYER metal2 ;
      RECT 250.765 460.390 250.835 460.600 ;
    END
  END r0_rd_out[201]
  PIN r0_rd_out[202]
    DIRECTION OUTPUT ;
    USE SIGNAL ;
    SHAPE ABUTMENT ;
    PORT
      LAYER metal2 ;
      RECT 254.185 460.390 254.255 460.600 ;
    END
  END r0_rd_out[202]
  PIN r0_rd_out[203]
    DIRECTION OUTPUT ;
    USE SIGNAL ;
    SHAPE ABUTMENT ;
    PORT
      LAYER metal2 ;
      RECT 257.605 460.390 257.675 460.600 ;
    END
  END r0_rd_out[203]
  PIN r0_rd_out[204]
    DIRECTION OUTPUT ;
    USE SIGNAL ;
    SHAPE ABUTMENT ;
    PORT
      LAYER metal2 ;
      RECT 261.025 460.390 261.095 460.600 ;
    END
  END r0_rd_out[204]
  PIN r0_rd_out[205]
    DIRECTION OUTPUT ;
    USE SIGNAL ;
    SHAPE ABUTMENT ;
    PORT
      LAYER metal2 ;
      RECT 264.445 460.390 264.515 460.600 ;
    END
  END r0_rd_out[205]
  PIN r0_rd_out[206]
    DIRECTION OUTPUT ;
    USE SIGNAL ;
    SHAPE ABUTMENT ;
    PORT
      LAYER metal2 ;
      RECT 267.865 460.390 267.935 460.600 ;
    END
  END r0_rd_out[206]
  PIN r0_rd_out[207]
    DIRECTION OUTPUT ;
    USE SIGNAL ;
    SHAPE ABUTMENT ;
    PORT
      LAYER metal2 ;
      RECT 271.285 460.390 271.355 460.600 ;
    END
  END r0_rd_out[207]
  PIN r0_rd_out[208]
    DIRECTION OUTPUT ;
    USE SIGNAL ;
    SHAPE ABUTMENT ;
    PORT
      LAYER metal2 ;
      RECT 274.705 460.390 274.775 460.600 ;
    END
  END r0_rd_out[208]
  PIN r0_rd_out[209]
    DIRECTION OUTPUT ;
    USE SIGNAL ;
    SHAPE ABUTMENT ;
    PORT
      LAYER metal2 ;
      RECT 278.125 460.390 278.195 460.600 ;
    END
  END r0_rd_out[209]
  PIN r0_rd_out[210]
    DIRECTION OUTPUT ;
    USE SIGNAL ;
    SHAPE ABUTMENT ;
    PORT
      LAYER metal2 ;
      RECT 281.545 460.390 281.615 460.600 ;
    END
  END r0_rd_out[210]
  PIN r0_rd_out[211]
    DIRECTION OUTPUT ;
    USE SIGNAL ;
    SHAPE ABUTMENT ;
    PORT
      LAYER metal2 ;
      RECT 284.965 460.390 285.035 460.600 ;
    END
  END r0_rd_out[211]
  PIN r0_rd_out[212]
    DIRECTION OUTPUT ;
    USE SIGNAL ;
    SHAPE ABUTMENT ;
    PORT
      LAYER metal2 ;
      RECT 288.385 460.390 288.455 460.600 ;
    END
  END r0_rd_out[212]
  PIN r0_rd_out[213]
    DIRECTION OUTPUT ;
    USE SIGNAL ;
    SHAPE ABUTMENT ;
    PORT
      LAYER metal2 ;
      RECT 291.805 460.390 291.875 460.600 ;
    END
  END r0_rd_out[213]
  PIN r0_rd_out[214]
    DIRECTION OUTPUT ;
    USE SIGNAL ;
    SHAPE ABUTMENT ;
    PORT
      LAYER metal2 ;
      RECT 295.225 460.390 295.295 460.600 ;
    END
  END r0_rd_out[214]
  PIN r0_rd_out[215]
    DIRECTION OUTPUT ;
    USE SIGNAL ;
    SHAPE ABUTMENT ;
    PORT
      LAYER metal2 ;
      RECT 298.645 460.390 298.715 460.600 ;
    END
  END r0_rd_out[215]
  PIN r0_rd_out[216]
    DIRECTION OUTPUT ;
    USE SIGNAL ;
    SHAPE ABUTMENT ;
    PORT
      LAYER metal2 ;
      RECT 302.065 460.390 302.135 460.600 ;
    END
  END r0_rd_out[216]
  PIN r0_rd_out[217]
    DIRECTION OUTPUT ;
    USE SIGNAL ;
    SHAPE ABUTMENT ;
    PORT
      LAYER metal2 ;
      RECT 305.485 460.390 305.555 460.600 ;
    END
  END r0_rd_out[217]
  PIN r0_rd_out[218]
    DIRECTION OUTPUT ;
    USE SIGNAL ;
    SHAPE ABUTMENT ;
    PORT
      LAYER metal2 ;
      RECT 308.905 460.390 308.975 460.600 ;
    END
  END r0_rd_out[218]
  PIN r0_rd_out[219]
    DIRECTION OUTPUT ;
    USE SIGNAL ;
    SHAPE ABUTMENT ;
    PORT
      LAYER metal2 ;
      RECT 312.325 460.390 312.395 460.600 ;
    END
  END r0_rd_out[219]
  PIN r0_rd_out[220]
    DIRECTION OUTPUT ;
    USE SIGNAL ;
    SHAPE ABUTMENT ;
    PORT
      LAYER metal2 ;
      RECT 315.745 460.390 315.815 460.600 ;
    END
  END r0_rd_out[220]
  PIN r0_rd_out[221]
    DIRECTION OUTPUT ;
    USE SIGNAL ;
    SHAPE ABUTMENT ;
    PORT
      LAYER metal2 ;
      RECT 319.165 460.390 319.235 460.600 ;
    END
  END r0_rd_out[221]
  PIN r0_rd_out[222]
    DIRECTION OUTPUT ;
    USE SIGNAL ;
    SHAPE ABUTMENT ;
    PORT
      LAYER metal2 ;
      RECT 322.585 460.390 322.655 460.600 ;
    END
  END r0_rd_out[222]
  PIN r0_rd_out[223]
    DIRECTION OUTPUT ;
    USE SIGNAL ;
    SHAPE ABUTMENT ;
    PORT
      LAYER metal2 ;
      RECT 326.005 460.390 326.075 460.600 ;
    END
  END r0_rd_out[223]
  PIN r0_rd_out[224]
    DIRECTION OUTPUT ;
    USE SIGNAL ;
    SHAPE ABUTMENT ;
    PORT
      LAYER metal2 ;
      RECT 329.425 460.390 329.495 460.600 ;
    END
  END r0_rd_out[224]
  PIN r0_rd_out[225]
    DIRECTION OUTPUT ;
    USE SIGNAL ;
    SHAPE ABUTMENT ;
    PORT
      LAYER metal2 ;
      RECT 332.845 460.390 332.915 460.600 ;
    END
  END r0_rd_out[225]
  PIN r0_rd_out[226]
    DIRECTION OUTPUT ;
    USE SIGNAL ;
    SHAPE ABUTMENT ;
    PORT
      LAYER metal2 ;
      RECT 336.265 460.390 336.335 460.600 ;
    END
  END r0_rd_out[226]
  PIN r0_rd_out[227]
    DIRECTION OUTPUT ;
    USE SIGNAL ;
    SHAPE ABUTMENT ;
    PORT
      LAYER metal2 ;
      RECT 339.685 460.390 339.755 460.600 ;
    END
  END r0_rd_out[227]
  PIN r0_rd_out[228]
    DIRECTION OUTPUT ;
    USE SIGNAL ;
    SHAPE ABUTMENT ;
    PORT
      LAYER metal2 ;
      RECT 343.105 460.390 343.175 460.600 ;
    END
  END r0_rd_out[228]
  PIN r0_rd_out[229]
    DIRECTION OUTPUT ;
    USE SIGNAL ;
    SHAPE ABUTMENT ;
    PORT
      LAYER metal2 ;
      RECT 346.525 460.390 346.595 460.600 ;
    END
  END r0_rd_out[229]
  PIN r0_rd_out[230]
    DIRECTION OUTPUT ;
    USE SIGNAL ;
    SHAPE ABUTMENT ;
    PORT
      LAYER metal2 ;
      RECT 349.945 460.390 350.015 460.600 ;
    END
  END r0_rd_out[230]
  PIN r0_rd_out[231]
    DIRECTION OUTPUT ;
    USE SIGNAL ;
    SHAPE ABUTMENT ;
    PORT
      LAYER metal2 ;
      RECT 353.365 460.390 353.435 460.600 ;
    END
  END r0_rd_out[231]
  PIN r0_rd_out[232]
    DIRECTION OUTPUT ;
    USE SIGNAL ;
    SHAPE ABUTMENT ;
    PORT
      LAYER metal2 ;
      RECT 356.785 460.390 356.855 460.600 ;
    END
  END r0_rd_out[232]
  PIN r0_rd_out[233]
    DIRECTION OUTPUT ;
    USE SIGNAL ;
    SHAPE ABUTMENT ;
    PORT
      LAYER metal2 ;
      RECT 360.205 460.390 360.275 460.600 ;
    END
  END r0_rd_out[233]
  PIN r0_rd_out[234]
    DIRECTION OUTPUT ;
    USE SIGNAL ;
    SHAPE ABUTMENT ;
    PORT
      LAYER metal2 ;
      RECT 363.625 460.390 363.695 460.600 ;
    END
  END r0_rd_out[234]
  PIN r0_rd_out[235]
    DIRECTION OUTPUT ;
    USE SIGNAL ;
    SHAPE ABUTMENT ;
    PORT
      LAYER metal2 ;
      RECT 367.045 460.390 367.115 460.600 ;
    END
  END r0_rd_out[235]
  PIN r0_rd_out[236]
    DIRECTION OUTPUT ;
    USE SIGNAL ;
    SHAPE ABUTMENT ;
    PORT
      LAYER metal2 ;
      RECT 370.465 460.390 370.535 460.600 ;
    END
  END r0_rd_out[236]
  PIN r0_rd_out[237]
    DIRECTION OUTPUT ;
    USE SIGNAL ;
    SHAPE ABUTMENT ;
    PORT
      LAYER metal2 ;
      RECT 373.885 460.390 373.955 460.600 ;
    END
  END r0_rd_out[237]
  PIN r0_rd_out[238]
    DIRECTION OUTPUT ;
    USE SIGNAL ;
    SHAPE ABUTMENT ;
    PORT
      LAYER metal2 ;
      RECT 377.305 460.390 377.375 460.600 ;
    END
  END r0_rd_out[238]
  PIN r0_rd_out[239]
    DIRECTION OUTPUT ;
    USE SIGNAL ;
    SHAPE ABUTMENT ;
    PORT
      LAYER metal2 ;
      RECT 380.725 460.390 380.795 460.600 ;
    END
  END r0_rd_out[239]
  PIN r0_rd_out[240]
    DIRECTION OUTPUT ;
    USE SIGNAL ;
    SHAPE ABUTMENT ;
    PORT
      LAYER metal2 ;
      RECT 384.145 460.390 384.215 460.600 ;
    END
  END r0_rd_out[240]
  PIN r0_rd_out[241]
    DIRECTION OUTPUT ;
    USE SIGNAL ;
    SHAPE ABUTMENT ;
    PORT
      LAYER metal2 ;
      RECT 387.565 460.390 387.635 460.600 ;
    END
  END r0_rd_out[241]
  PIN r0_rd_out[242]
    DIRECTION OUTPUT ;
    USE SIGNAL ;
    SHAPE ABUTMENT ;
    PORT
      LAYER metal2 ;
      RECT 390.985 460.390 391.055 460.600 ;
    END
  END r0_rd_out[242]
  PIN r0_rd_out[243]
    DIRECTION OUTPUT ;
    USE SIGNAL ;
    SHAPE ABUTMENT ;
    PORT
      LAYER metal2 ;
      RECT 394.405 460.390 394.475 460.600 ;
    END
  END r0_rd_out[243]
  PIN r0_rd_out[244]
    DIRECTION OUTPUT ;
    USE SIGNAL ;
    SHAPE ABUTMENT ;
    PORT
      LAYER metal2 ;
      RECT 397.825 460.390 397.895 460.600 ;
    END
  END r0_rd_out[244]
  PIN r0_rd_out[245]
    DIRECTION OUTPUT ;
    USE SIGNAL ;
    SHAPE ABUTMENT ;
    PORT
      LAYER metal2 ;
      RECT 401.245 460.390 401.315 460.600 ;
    END
  END r0_rd_out[245]
  PIN r0_rd_out[246]
    DIRECTION OUTPUT ;
    USE SIGNAL ;
    SHAPE ABUTMENT ;
    PORT
      LAYER metal2 ;
      RECT 404.665 460.390 404.735 460.600 ;
    END
  END r0_rd_out[246]
  PIN r0_rd_out[247]
    DIRECTION OUTPUT ;
    USE SIGNAL ;
    SHAPE ABUTMENT ;
    PORT
      LAYER metal2 ;
      RECT 408.085 460.390 408.155 460.600 ;
    END
  END r0_rd_out[247]
  PIN r0_rd_out[248]
    DIRECTION OUTPUT ;
    USE SIGNAL ;
    SHAPE ABUTMENT ;
    PORT
      LAYER metal2 ;
      RECT 411.505 460.390 411.575 460.600 ;
    END
  END r0_rd_out[248]
  PIN r0_rd_out[249]
    DIRECTION OUTPUT ;
    USE SIGNAL ;
    SHAPE ABUTMENT ;
    PORT
      LAYER metal2 ;
      RECT 414.925 460.390 414.995 460.600 ;
    END
  END r0_rd_out[249]
  PIN r0_rd_out[250]
    DIRECTION OUTPUT ;
    USE SIGNAL ;
    SHAPE ABUTMENT ;
    PORT
      LAYER metal2 ;
      RECT 418.345 460.390 418.415 460.600 ;
    END
  END r0_rd_out[250]
  PIN r0_rd_out[251]
    DIRECTION OUTPUT ;
    USE SIGNAL ;
    SHAPE ABUTMENT ;
    PORT
      LAYER metal2 ;
      RECT 421.765 460.390 421.835 460.600 ;
    END
  END r0_rd_out[251]
  PIN r0_rd_out[252]
    DIRECTION OUTPUT ;
    USE SIGNAL ;
    SHAPE ABUTMENT ;
    PORT
      LAYER metal2 ;
      RECT 425.185 460.390 425.255 460.600 ;
    END
  END r0_rd_out[252]
  PIN r0_rd_out[253]
    DIRECTION OUTPUT ;
    USE SIGNAL ;
    SHAPE ABUTMENT ;
    PORT
      LAYER metal2 ;
      RECT 428.605 460.390 428.675 460.600 ;
    END
  END r0_rd_out[253]
  PIN r0_rd_out[254]
    DIRECTION OUTPUT ;
    USE SIGNAL ;
    SHAPE ABUTMENT ;
    PORT
      LAYER metal2 ;
      RECT 432.025 460.390 432.095 460.600 ;
    END
  END r0_rd_out[254]
  PIN r0_rd_out[255]
    DIRECTION OUTPUT ;
    USE SIGNAL ;
    SHAPE ABUTMENT ;
    PORT
      LAYER metal2 ;
      RECT 435.445 460.390 435.515 460.600 ;
    END
  END r0_rd_out[255]
  PIN w0_addr_in[0]
    DIRECTION INPUT ;
    USE SIGNAL ;
    SHAPE ABUTMENT ;
    PORT
      LAYER metal3 ;
      RECT 0.000 404.005 0.210 404.075 ;
    END
  END w0_addr_in[0]
  PIN w0_addr_in[1]
    DIRECTION INPUT ;
    USE SIGNAL ;
    SHAPE ABUTMENT ;
    PORT
      LAYER metal3 ;
      RECT 0.000 410.305 0.210 410.375 ;
    END
  END w0_addr_in[1]
  PIN w0_addr_in[2]
    DIRECTION INPUT ;
    USE SIGNAL ;
    SHAPE ABUTMENT ;
    PORT
      LAYER metal3 ;
      RECT 0.000 416.605 0.210 416.675 ;
    END
  END w0_addr_in[2]
  PIN w0_addr_in[3]
    DIRECTION INPUT ;
    USE SIGNAL ;
    SHAPE ABUTMENT ;
    PORT
      LAYER metal3 ;
      RECT 0.000 422.905 0.210 422.975 ;
    END
  END w0_addr_in[3]
  PIN w0_addr_in[4]
    DIRECTION INPUT ;
    USE SIGNAL ;
    SHAPE ABUTMENT ;
    PORT
      LAYER metal3 ;
      RECT 467.190 404.005 467.400 404.075 ;
    END
  END w0_addr_in[4]
  PIN w0_addr_in[5]
    DIRECTION INPUT ;
    USE SIGNAL ;
    SHAPE ABUTMENT ;
    PORT
      LAYER metal3 ;
      RECT 467.190 410.305 467.400 410.375 ;
    END
  END w0_addr_in[5]
  PIN w0_addr_in[6]
    DIRECTION INPUT ;
    USE SIGNAL ;
    SHAPE ABUTMENT ;
    PORT
      LAYER metal3 ;
      RECT 467.190 416.605 467.400 416.675 ;
    END
  END w0_addr_in[6]
  PIN w0_addr_in[7]
    DIRECTION INPUT ;
    USE SIGNAL ;
    SHAPE ABUTMENT ;
    PORT
      LAYER metal3 ;
      RECT 467.190 422.905 467.400 422.975 ;
    END
  END w0_addr_in[7]
  PIN r0_addr_in[0]
    DIRECTION INPUT ;
    USE SIGNAL ;
    SHAPE ABUTMENT ;
    PORT
      LAYER metal3 ;
      RECT 0.000 429.205 0.210 429.275 ;
    END
  END r0_addr_in[0]
  PIN r0_addr_in[1]
    DIRECTION INPUT ;
    USE SIGNAL ;
    SHAPE ABUTMENT ;
    PORT
      LAYER metal3 ;
      RECT 0.000 435.505 0.210 435.575 ;
    END
  END r0_addr_in[1]
  PIN r0_addr_in[2]
    DIRECTION INPUT ;
    USE SIGNAL ;
    SHAPE ABUTMENT ;
    PORT
      LAYER metal3 ;
      RECT 0.000 441.805 0.210 441.875 ;
    END
  END r0_addr_in[2]
  PIN r0_addr_in[3]
    DIRECTION INPUT ;
    USE SIGNAL ;
    SHAPE ABUTMENT ;
    PORT
      LAYER metal3 ;
      RECT 0.000 448.105 0.210 448.175 ;
    END
  END r0_addr_in[3]
  PIN r0_addr_in[4]
    DIRECTION INPUT ;
    USE SIGNAL ;
    SHAPE ABUTMENT ;
    PORT
      LAYER metal3 ;
      RECT 467.190 429.205 467.400 429.275 ;
    END
  END r0_addr_in[4]
  PIN r0_addr_in[5]
    DIRECTION INPUT ;
    USE SIGNAL ;
    SHAPE ABUTMENT ;
    PORT
      LAYER metal3 ;
      RECT 467.190 435.505 467.400 435.575 ;
    END
  END r0_addr_in[5]
  PIN r0_addr_in[6]
    DIRECTION INPUT ;
    USE SIGNAL ;
    SHAPE ABUTMENT ;
    PORT
      LAYER metal3 ;
      RECT 467.190 441.805 467.400 441.875 ;
    END
  END r0_addr_in[6]
  PIN r0_addr_in[7]
    DIRECTION INPUT ;
    USE SIGNAL ;
    SHAPE ABUTMENT ;
    PORT
      LAYER metal3 ;
      RECT 467.190 448.105 467.400 448.175 ;
    END
  END r0_addr_in[7]
  PIN w0_we_in
    DIRECTION INPUT ;
    USE SIGNAL ;
    SHAPE ABUTMENT ;
    PORT
      LAYER metal2 ;
      RECT 438.865 460.390 438.935 460.600 ;
    END
  END w0_we_in
  PIN w0_ce_in
    DIRECTION INPUT ;
    USE SIGNAL ;
    SHAPE ABUTMENT ;
    PORT
      LAYER metal2 ;
      RECT 442.285 460.390 442.355 460.600 ;
    END
  END w0_ce_in
  PIN w0_clk
    DIRECTION INPUT ;
    USE SIGNAL ;
    SHAPE ABUTMENT ;
    PORT
      LAYER metal2 ;
      RECT 445.705 460.390 445.775 460.600 ;
    END
  END w0_clk
  PIN r0_ce_in
    DIRECTION INPUT ;
    USE SIGNAL ;
    SHAPE ABUTMENT ;
    PORT
      LAYER metal2 ;
      RECT 449.125 460.390 449.195 460.600 ;
    END
  END r0_ce_in
  PIN r0_clk
    DIRECTION INPUT ;
    USE SIGNAL ;
    SHAPE ABUTMENT ;
    PORT
      LAYER metal2 ;
      RECT 452.545 460.390 452.615 460.600 ;
    END
  END r0_clk
  PIN VSS
    DIRECTION INOUT ;
    USE GROUND ;
    PORT
      LAYER metal4 ;
      RECT 1.000 0.840 1.280 459.760 ;
      RECT 3.240 0.840 3.520 459.760 ;
      RECT 5.480 0.840 5.760 459.760 ;
      RECT 7.720 0.840 8.000 459.760 ;
      RECT 9.960 0.840 10.240 459.760 ;
      RECT 12.200 0.840 12.480 459.760 ;
      RECT 14.440 0.840 14.720 459.760 ;
      RECT 16.680 0.840 16.960 459.760 ;
      RECT 18.920 0.840 19.200 459.760 ;
      RECT 21.160 0.840 21.440 459.760 ;
      RECT 23.400 0.840 23.680 459.760 ;
      RECT 25.640 0.840 25.920 459.760 ;
      RECT 27.880 0.840 28.160 459.760 ;
      RECT 30.120 0.840 30.400 459.760 ;
      RECT 32.360 0.840 32.640 459.760 ;
      RECT 34.600 0.840 34.880 459.760 ;
      RECT 36.840 0.840 37.120 459.760 ;
      RECT 39.080 0.840 39.360 459.760 ;
      RECT 41.320 0.840 41.600 459.760 ;
      RECT 43.560 0.840 43.840 459.760 ;
      RECT 45.800 0.840 46.080 459.760 ;
      RECT 48.040 0.840 48.320 459.760 ;
      RECT 50.280 0.840 50.560 459.760 ;
      RECT 52.520 0.840 52.800 459.760 ;
      RECT 54.760 0.840 55.040 459.760 ;
      RECT 57.000 0.840 57.280 459.760 ;
      RECT 59.240 0.840 59.520 459.760 ;
      RECT 61.480 0.840 61.760 459.760 ;
      RECT 63.720 0.840 64.000 459.760 ;
      RECT 65.960 0.840 66.240 459.760 ;
      RECT 68.200 0.840 68.480 459.760 ;
      RECT 70.440 0.840 70.720 459.760 ;
      RECT 72.680 0.840 72.960 459.760 ;
      RECT 74.920 0.840 75.200 459.760 ;
      RECT 77.160 0.840 77.440 459.760 ;
      RECT 79.400 0.840 79.680 459.760 ;
      RECT 81.640 0.840 81.920 459.760 ;
      RECT 83.880 0.840 84.160 459.760 ;
      RECT 86.120 0.840 86.400 459.760 ;
      RECT 88.360 0.840 88.640 459.760 ;
      RECT 90.600 0.840 90.880 459.760 ;
      RECT 92.840 0.840 93.120 459.760 ;
      RECT 95.080 0.840 95.360 459.760 ;
      RECT 97.320 0.840 97.600 459.760 ;
      RECT 99.560 0.840 99.840 459.760 ;
      RECT 101.800 0.840 102.080 459.760 ;
      RECT 104.040 0.840 104.320 459.760 ;
      RECT 106.280 0.840 106.560 459.760 ;
      RECT 108.520 0.840 108.800 459.760 ;
      RECT 110.760 0.840 111.040 459.760 ;
      RECT 113.000 0.840 113.280 459.760 ;
      RECT 115.240 0.840 115.520 459.760 ;
      RECT 117.480 0.840 117.760 459.760 ;
      RECT 119.720 0.840 120.000 459.760 ;
      RECT 121.960 0.840 122.240 459.760 ;
      RECT 124.200 0.840 124.480 459.760 ;
      RECT 126.440 0.840 126.720 459.760 ;
      RECT 128.680 0.840 128.960 459.760 ;
      RECT 130.920 0.840 131.200 459.760 ;
      RECT 133.160 0.840 133.440 459.760 ;
      RECT 135.400 0.840 135.680 459.760 ;
      RECT 137.640 0.840 137.920 459.760 ;
      RECT 139.880 0.840 140.160 459.760 ;
      RECT 142.120 0.840 142.400 459.760 ;
      RECT 144.360 0.840 144.640 459.760 ;
      RECT 146.600 0.840 146.880 459.760 ;
      RECT 148.840 0.840 149.120 459.760 ;
      RECT 151.080 0.840 151.360 459.760 ;
      RECT 153.320 0.840 153.600 459.760 ;
      RECT 155.560 0.840 155.840 459.760 ;
      RECT 157.800 0.840 158.080 459.760 ;
      RECT 160.040 0.840 160.320 459.760 ;
      RECT 162.280 0.840 162.560 459.760 ;
      RECT 164.520 0.840 164.800 459.760 ;
      RECT 166.760 0.840 167.040 459.760 ;
      RECT 169.000 0.840 169.280 459.760 ;
      RECT 171.240 0.840 171.520 459.760 ;
      RECT 173.480 0.840 173.760 459.760 ;
      RECT 175.720 0.840 176.000 459.760 ;
      RECT 177.960 0.840 178.240 459.760 ;
      RECT 180.200 0.840 180.480 459.760 ;
      RECT 182.440 0.840 182.720 459.760 ;
      RECT 184.680 0.840 184.960 459.760 ;
      RECT 186.920 0.840 187.200 459.760 ;
      RECT 189.160 0.840 189.440 459.760 ;
      RECT 191.400 0.840 191.680 459.760 ;
      RECT 193.640 0.840 193.920 459.760 ;
      RECT 195.880 0.840 196.160 459.760 ;
      RECT 198.120 0.840 198.400 459.760 ;
      RECT 200.360 0.840 200.640 459.760 ;
      RECT 202.600 0.840 202.880 459.760 ;
      RECT 204.840 0.840 205.120 459.760 ;
      RECT 207.080 0.840 207.360 459.760 ;
      RECT 209.320 0.840 209.600 459.760 ;
      RECT 211.560 0.840 211.840 459.760 ;
      RECT 213.800 0.840 214.080 459.760 ;
      RECT 216.040 0.840 216.320 459.760 ;
      RECT 218.280 0.840 218.560 459.760 ;
      RECT 220.520 0.840 220.800 459.760 ;
      RECT 222.760 0.840 223.040 459.760 ;
      RECT 225.000 0.840 225.280 459.760 ;
      RECT 227.240 0.840 227.520 459.760 ;
      RECT 229.480 0.840 229.760 459.760 ;
      RECT 231.720 0.840 232.000 459.760 ;
      RECT 233.960 0.840 234.240 459.760 ;
      RECT 236.200 0.840 236.480 459.760 ;
      RECT 238.440 0.840 238.720 459.760 ;
      RECT 240.680 0.840 240.960 459.760 ;
      RECT 242.920 0.840 243.200 459.760 ;
      RECT 245.160 0.840 245.440 459.760 ;
      RECT 247.400 0.840 247.680 459.760 ;
      RECT 249.640 0.840 249.920 459.760 ;
      RECT 251.880 0.840 252.160 459.760 ;
      RECT 254.120 0.840 254.400 459.760 ;
      RECT 256.360 0.840 256.640 459.760 ;
      RECT 258.600 0.840 258.880 459.760 ;
      RECT 260.840 0.840 261.120 459.760 ;
      RECT 263.080 0.840 263.360 459.760 ;
      RECT 265.320 0.840 265.600 459.760 ;
      RECT 267.560 0.840 267.840 459.760 ;
      RECT 269.800 0.840 270.080 459.760 ;
      RECT 272.040 0.840 272.320 459.760 ;
      RECT 274.280 0.840 274.560 459.760 ;
      RECT 276.520 0.840 276.800 459.760 ;
      RECT 278.760 0.840 279.040 459.760 ;
      RECT 281.000 0.840 281.280 459.760 ;
      RECT 283.240 0.840 283.520 459.760 ;
      RECT 285.480 0.840 285.760 459.760 ;
      RECT 287.720 0.840 288.000 459.760 ;
      RECT 289.960 0.840 290.240 459.760 ;
      RECT 292.200 0.840 292.480 459.760 ;
      RECT 294.440 0.840 294.720 459.760 ;
      RECT 296.680 0.840 296.960 459.760 ;
      RECT 298.920 0.840 299.200 459.760 ;
      RECT 301.160 0.840 301.440 459.760 ;
      RECT 303.400 0.840 303.680 459.760 ;
      RECT 305.640 0.840 305.920 459.760 ;
      RECT 307.880 0.840 308.160 459.760 ;
      RECT 310.120 0.840 310.400 459.760 ;
      RECT 312.360 0.840 312.640 459.760 ;
      RECT 314.600 0.840 314.880 459.760 ;
      RECT 316.840 0.840 317.120 459.760 ;
      RECT 319.080 0.840 319.360 459.760 ;
      RECT 321.320 0.840 321.600 459.760 ;
      RECT 323.560 0.840 323.840 459.760 ;
      RECT 325.800 0.840 326.080 459.760 ;
      RECT 328.040 0.840 328.320 459.760 ;
      RECT 330.280 0.840 330.560 459.760 ;
      RECT 332.520 0.840 332.800 459.760 ;
      RECT 334.760 0.840 335.040 459.760 ;
      RECT 337.000 0.840 337.280 459.760 ;
      RECT 339.240 0.840 339.520 459.760 ;
      RECT 341.480 0.840 341.760 459.760 ;
      RECT 343.720 0.840 344.000 459.760 ;
      RECT 345.960 0.840 346.240 459.760 ;
      RECT 348.200 0.840 348.480 459.760 ;
      RECT 350.440 0.840 350.720 459.760 ;
      RECT 352.680 0.840 352.960 459.760 ;
      RECT 354.920 0.840 355.200 459.760 ;
      RECT 357.160 0.840 357.440 459.760 ;
      RECT 359.400 0.840 359.680 459.760 ;
      RECT 361.640 0.840 361.920 459.760 ;
      RECT 363.880 0.840 364.160 459.760 ;
      RECT 366.120 0.840 366.400 459.760 ;
      RECT 368.360 0.840 368.640 459.760 ;
      RECT 370.600 0.840 370.880 459.760 ;
      RECT 372.840 0.840 373.120 459.760 ;
      RECT 375.080 0.840 375.360 459.760 ;
      RECT 377.320 0.840 377.600 459.760 ;
      RECT 379.560 0.840 379.840 459.760 ;
      RECT 381.800 0.840 382.080 459.760 ;
      RECT 384.040 0.840 384.320 459.760 ;
      RECT 386.280 0.840 386.560 459.760 ;
      RECT 388.520 0.840 388.800 459.760 ;
      RECT 390.760 0.840 391.040 459.760 ;
      RECT 393.000 0.840 393.280 459.760 ;
      RECT 395.240 0.840 395.520 459.760 ;
      RECT 397.480 0.840 397.760 459.760 ;
      RECT 399.720 0.840 400.000 459.760 ;
      RECT 401.960 0.840 402.240 459.760 ;
      RECT 404.200 0.840 404.480 459.760 ;
      RECT 406.440 0.840 406.720 459.760 ;
      RECT 408.680 0.840 408.960 459.760 ;
      RECT 410.920 0.840 411.200 459.760 ;
      RECT 413.160 0.840 413.440 459.760 ;
      RECT 415.400 0.840 415.680 459.760 ;
      RECT 417.640 0.840 417.920 459.760 ;
      RECT 419.880 0.840 420.160 459.760 ;
      RECT 422.120 0.840 422.400 459.760 ;
      RECT 424.360 0.840 424.640 459.760 ;
      RECT 426.600 0.840 426.880 459.760 ;
      RECT 428.840 0.840 429.120 459.760 ;
      RECT 431.080 0.840 431.360 459.760 ;
      RECT 433.320 0.840 433.600 459.760 ;
      RECT 435.560 0.840 435.840 459.760 ;
      RECT 437.800 0.840 438.080 459.760 ;
      RECT 440.040 0.840 440.320 459.760 ;
      RECT 442.280 0.840 442.560 459.760 ;
      RECT 444.520 0.840 444.800 459.760 ;
      RECT 446.760 0.840 447.040 459.760 ;
      RECT 449.000 0.840 449.280 459.760 ;
      RECT 451.240 0.840 451.520 459.760 ;
      RECT 453.480 0.840 453.760 459.760 ;
      RECT 455.720 0.840 456.000 459.760 ;
      RECT 457.960 0.840 458.240 459.760 ;
      RECT 460.200 0.840 460.480 459.760 ;
      RECT 462.440 0.840 462.720 459.760 ;
      RECT 464.680 0.840 464.960 459.760 ;
      RECT 466.920 0.840 467.200 459.760 ;
    END
  END VSS
  PIN VDD
    DIRECTION INOUT ;
    USE POWER ;
    PORT
      LAYER metal4 ;
      RECT 1.000 0.840 1.280 459.760 ;
      RECT 3.240 0.840 3.520 459.760 ;
      RECT 5.480 0.840 5.760 459.760 ;
      RECT 7.720 0.840 8.000 459.760 ;
      RECT 9.960 0.840 10.240 459.760 ;
      RECT 12.200 0.840 12.480 459.760 ;
      RECT 14.440 0.840 14.720 459.760 ;
      RECT 16.680 0.840 16.960 459.760 ;
      RECT 18.920 0.840 19.200 459.760 ;
      RECT 21.160 0.840 21.440 459.760 ;
      RECT 23.400 0.840 23.680 459.760 ;
      RECT 25.640 0.840 25.920 459.760 ;
      RECT 27.880 0.840 28.160 459.760 ;
      RECT 30.120 0.840 30.400 459.760 ;
      RECT 32.360 0.840 32.640 459.760 ;
      RECT 34.600 0.840 34.880 459.760 ;
      RECT 36.840 0.840 37.120 459.760 ;
      RECT 39.080 0.840 39.360 459.760 ;
      RECT 41.320 0.840 41.600 459.760 ;
      RECT 43.560 0.840 43.840 459.760 ;
      RECT 45.800 0.840 46.080 459.760 ;
      RECT 48.040 0.840 48.320 459.760 ;
      RECT 50.280 0.840 50.560 459.760 ;
      RECT 52.520 0.840 52.800 459.760 ;
      RECT 54.760 0.840 55.040 459.760 ;
      RECT 57.000 0.840 57.280 459.760 ;
      RECT 59.240 0.840 59.520 459.760 ;
      RECT 61.480 0.840 61.760 459.760 ;
      RECT 63.720 0.840 64.000 459.760 ;
      RECT 65.960 0.840 66.240 459.760 ;
      RECT 68.200 0.840 68.480 459.760 ;
      RECT 70.440 0.840 70.720 459.760 ;
      RECT 72.680 0.840 72.960 459.760 ;
      RECT 74.920 0.840 75.200 459.760 ;
      RECT 77.160 0.840 77.440 459.760 ;
      RECT 79.400 0.840 79.680 459.760 ;
      RECT 81.640 0.840 81.920 459.760 ;
      RECT 83.880 0.840 84.160 459.760 ;
      RECT 86.120 0.840 86.400 459.760 ;
      RECT 88.360 0.840 88.640 459.760 ;
      RECT 90.600 0.840 90.880 459.760 ;
      RECT 92.840 0.840 93.120 459.760 ;
      RECT 95.080 0.840 95.360 459.760 ;
      RECT 97.320 0.840 97.600 459.760 ;
      RECT 99.560 0.840 99.840 459.760 ;
      RECT 101.800 0.840 102.080 459.760 ;
      RECT 104.040 0.840 104.320 459.760 ;
      RECT 106.280 0.840 106.560 459.760 ;
      RECT 108.520 0.840 108.800 459.760 ;
      RECT 110.760 0.840 111.040 459.760 ;
      RECT 113.000 0.840 113.280 459.760 ;
      RECT 115.240 0.840 115.520 459.760 ;
      RECT 117.480 0.840 117.760 459.760 ;
      RECT 119.720 0.840 120.000 459.760 ;
      RECT 121.960 0.840 122.240 459.760 ;
      RECT 124.200 0.840 124.480 459.760 ;
      RECT 126.440 0.840 126.720 459.760 ;
      RECT 128.680 0.840 128.960 459.760 ;
      RECT 130.920 0.840 131.200 459.760 ;
      RECT 133.160 0.840 133.440 459.760 ;
      RECT 135.400 0.840 135.680 459.760 ;
      RECT 137.640 0.840 137.920 459.760 ;
      RECT 139.880 0.840 140.160 459.760 ;
      RECT 142.120 0.840 142.400 459.760 ;
      RECT 144.360 0.840 144.640 459.760 ;
      RECT 146.600 0.840 146.880 459.760 ;
      RECT 148.840 0.840 149.120 459.760 ;
      RECT 151.080 0.840 151.360 459.760 ;
      RECT 153.320 0.840 153.600 459.760 ;
      RECT 155.560 0.840 155.840 459.760 ;
      RECT 157.800 0.840 158.080 459.760 ;
      RECT 160.040 0.840 160.320 459.760 ;
      RECT 162.280 0.840 162.560 459.760 ;
      RECT 164.520 0.840 164.800 459.760 ;
      RECT 166.760 0.840 167.040 459.760 ;
      RECT 169.000 0.840 169.280 459.760 ;
      RECT 171.240 0.840 171.520 459.760 ;
      RECT 173.480 0.840 173.760 459.760 ;
      RECT 175.720 0.840 176.000 459.760 ;
      RECT 177.960 0.840 178.240 459.760 ;
      RECT 180.200 0.840 180.480 459.760 ;
      RECT 182.440 0.840 182.720 459.760 ;
      RECT 184.680 0.840 184.960 459.760 ;
      RECT 186.920 0.840 187.200 459.760 ;
      RECT 189.160 0.840 189.440 459.760 ;
      RECT 191.400 0.840 191.680 459.760 ;
      RECT 193.640 0.840 193.920 459.760 ;
      RECT 195.880 0.840 196.160 459.760 ;
      RECT 198.120 0.840 198.400 459.760 ;
      RECT 200.360 0.840 200.640 459.760 ;
      RECT 202.600 0.840 202.880 459.760 ;
      RECT 204.840 0.840 205.120 459.760 ;
      RECT 207.080 0.840 207.360 459.760 ;
      RECT 209.320 0.840 209.600 459.760 ;
      RECT 211.560 0.840 211.840 459.760 ;
      RECT 213.800 0.840 214.080 459.760 ;
      RECT 216.040 0.840 216.320 459.760 ;
      RECT 218.280 0.840 218.560 459.760 ;
      RECT 220.520 0.840 220.800 459.760 ;
      RECT 222.760 0.840 223.040 459.760 ;
      RECT 225.000 0.840 225.280 459.760 ;
      RECT 227.240 0.840 227.520 459.760 ;
      RECT 229.480 0.840 229.760 459.760 ;
      RECT 231.720 0.840 232.000 459.760 ;
      RECT 233.960 0.840 234.240 459.760 ;
      RECT 236.200 0.840 236.480 459.760 ;
      RECT 238.440 0.840 238.720 459.760 ;
      RECT 240.680 0.840 240.960 459.760 ;
      RECT 242.920 0.840 243.200 459.760 ;
      RECT 245.160 0.840 245.440 459.760 ;
      RECT 247.400 0.840 247.680 459.760 ;
      RECT 249.640 0.840 249.920 459.760 ;
      RECT 251.880 0.840 252.160 459.760 ;
      RECT 254.120 0.840 254.400 459.760 ;
      RECT 256.360 0.840 256.640 459.760 ;
      RECT 258.600 0.840 258.880 459.760 ;
      RECT 260.840 0.840 261.120 459.760 ;
      RECT 263.080 0.840 263.360 459.760 ;
      RECT 265.320 0.840 265.600 459.760 ;
      RECT 267.560 0.840 267.840 459.760 ;
      RECT 269.800 0.840 270.080 459.760 ;
      RECT 272.040 0.840 272.320 459.760 ;
      RECT 274.280 0.840 274.560 459.760 ;
      RECT 276.520 0.840 276.800 459.760 ;
      RECT 278.760 0.840 279.040 459.760 ;
      RECT 281.000 0.840 281.280 459.760 ;
      RECT 283.240 0.840 283.520 459.760 ;
      RECT 285.480 0.840 285.760 459.760 ;
      RECT 287.720 0.840 288.000 459.760 ;
      RECT 289.960 0.840 290.240 459.760 ;
      RECT 292.200 0.840 292.480 459.760 ;
      RECT 294.440 0.840 294.720 459.760 ;
      RECT 296.680 0.840 296.960 459.760 ;
      RECT 298.920 0.840 299.200 459.760 ;
      RECT 301.160 0.840 301.440 459.760 ;
      RECT 303.400 0.840 303.680 459.760 ;
      RECT 305.640 0.840 305.920 459.760 ;
      RECT 307.880 0.840 308.160 459.760 ;
      RECT 310.120 0.840 310.400 459.760 ;
      RECT 312.360 0.840 312.640 459.760 ;
      RECT 314.600 0.840 314.880 459.760 ;
      RECT 316.840 0.840 317.120 459.760 ;
      RECT 319.080 0.840 319.360 459.760 ;
      RECT 321.320 0.840 321.600 459.760 ;
      RECT 323.560 0.840 323.840 459.760 ;
      RECT 325.800 0.840 326.080 459.760 ;
      RECT 328.040 0.840 328.320 459.760 ;
      RECT 330.280 0.840 330.560 459.760 ;
      RECT 332.520 0.840 332.800 459.760 ;
      RECT 334.760 0.840 335.040 459.760 ;
      RECT 337.000 0.840 337.280 459.760 ;
      RECT 339.240 0.840 339.520 459.760 ;
      RECT 341.480 0.840 341.760 459.760 ;
      RECT 343.720 0.840 344.000 459.760 ;
      RECT 345.960 0.840 346.240 459.760 ;
      RECT 348.200 0.840 348.480 459.760 ;
      RECT 350.440 0.840 350.720 459.760 ;
      RECT 352.680 0.840 352.960 459.760 ;
      RECT 354.920 0.840 355.200 459.760 ;
      RECT 357.160 0.840 357.440 459.760 ;
      RECT 359.400 0.840 359.680 459.760 ;
      RECT 361.640 0.840 361.920 459.760 ;
      RECT 363.880 0.840 364.160 459.760 ;
      RECT 366.120 0.840 366.400 459.760 ;
      RECT 368.360 0.840 368.640 459.760 ;
      RECT 370.600 0.840 370.880 459.760 ;
      RECT 372.840 0.840 373.120 459.760 ;
      RECT 375.080 0.840 375.360 459.760 ;
      RECT 377.320 0.840 377.600 459.760 ;
      RECT 379.560 0.840 379.840 459.760 ;
      RECT 381.800 0.840 382.080 459.760 ;
      RECT 384.040 0.840 384.320 459.760 ;
      RECT 386.280 0.840 386.560 459.760 ;
      RECT 388.520 0.840 388.800 459.760 ;
      RECT 390.760 0.840 391.040 459.760 ;
      RECT 393.000 0.840 393.280 459.760 ;
      RECT 395.240 0.840 395.520 459.760 ;
      RECT 397.480 0.840 397.760 459.760 ;
      RECT 399.720 0.840 400.000 459.760 ;
      RECT 401.960 0.840 402.240 459.760 ;
      RECT 404.200 0.840 404.480 459.760 ;
      RECT 406.440 0.840 406.720 459.760 ;
      RECT 408.680 0.840 408.960 459.760 ;
      RECT 410.920 0.840 411.200 459.760 ;
      RECT 413.160 0.840 413.440 459.760 ;
      RECT 415.400 0.840 415.680 459.760 ;
      RECT 417.640 0.840 417.920 459.760 ;
      RECT 419.880 0.840 420.160 459.760 ;
      RECT 422.120 0.840 422.400 459.760 ;
      RECT 424.360 0.840 424.640 459.760 ;
      RECT 426.600 0.840 426.880 459.760 ;
      RECT 428.840 0.840 429.120 459.760 ;
      RECT 431.080 0.840 431.360 459.760 ;
      RECT 433.320 0.840 433.600 459.760 ;
      RECT 435.560 0.840 435.840 459.760 ;
      RECT 437.800 0.840 438.080 459.760 ;
      RECT 440.040 0.840 440.320 459.760 ;
      RECT 442.280 0.840 442.560 459.760 ;
      RECT 444.520 0.840 444.800 459.760 ;
      RECT 446.760 0.840 447.040 459.760 ;
      RECT 449.000 0.840 449.280 459.760 ;
      RECT 451.240 0.840 451.520 459.760 ;
      RECT 453.480 0.840 453.760 459.760 ;
      RECT 455.720 0.840 456.000 459.760 ;
      RECT 457.960 0.840 458.240 459.760 ;
      RECT 460.200 0.840 460.480 459.760 ;
      RECT 462.440 0.840 462.720 459.760 ;
      RECT 464.680 0.840 464.960 459.760 ;
      RECT 466.920 0.840 467.200 459.760 ;
    END
  END VDD
  OBS
    LAYER metal1 ;
    RECT 0 0 467.400 460.600 ;
    LAYER metal2 ;
    RECT 0 0 467.400 460.600 ;
    LAYER metal3 ;
    RECT 0 0 467.400 460.600 ;
    LAYER metal4 ;
    RECT 0 0 467.400 460.600 ;
    LAYER OVERLAP ;
    RECT 0 0 467.400 460.600 ;
  END
END fakeram_256x256_1r1w

END LIBRARY
